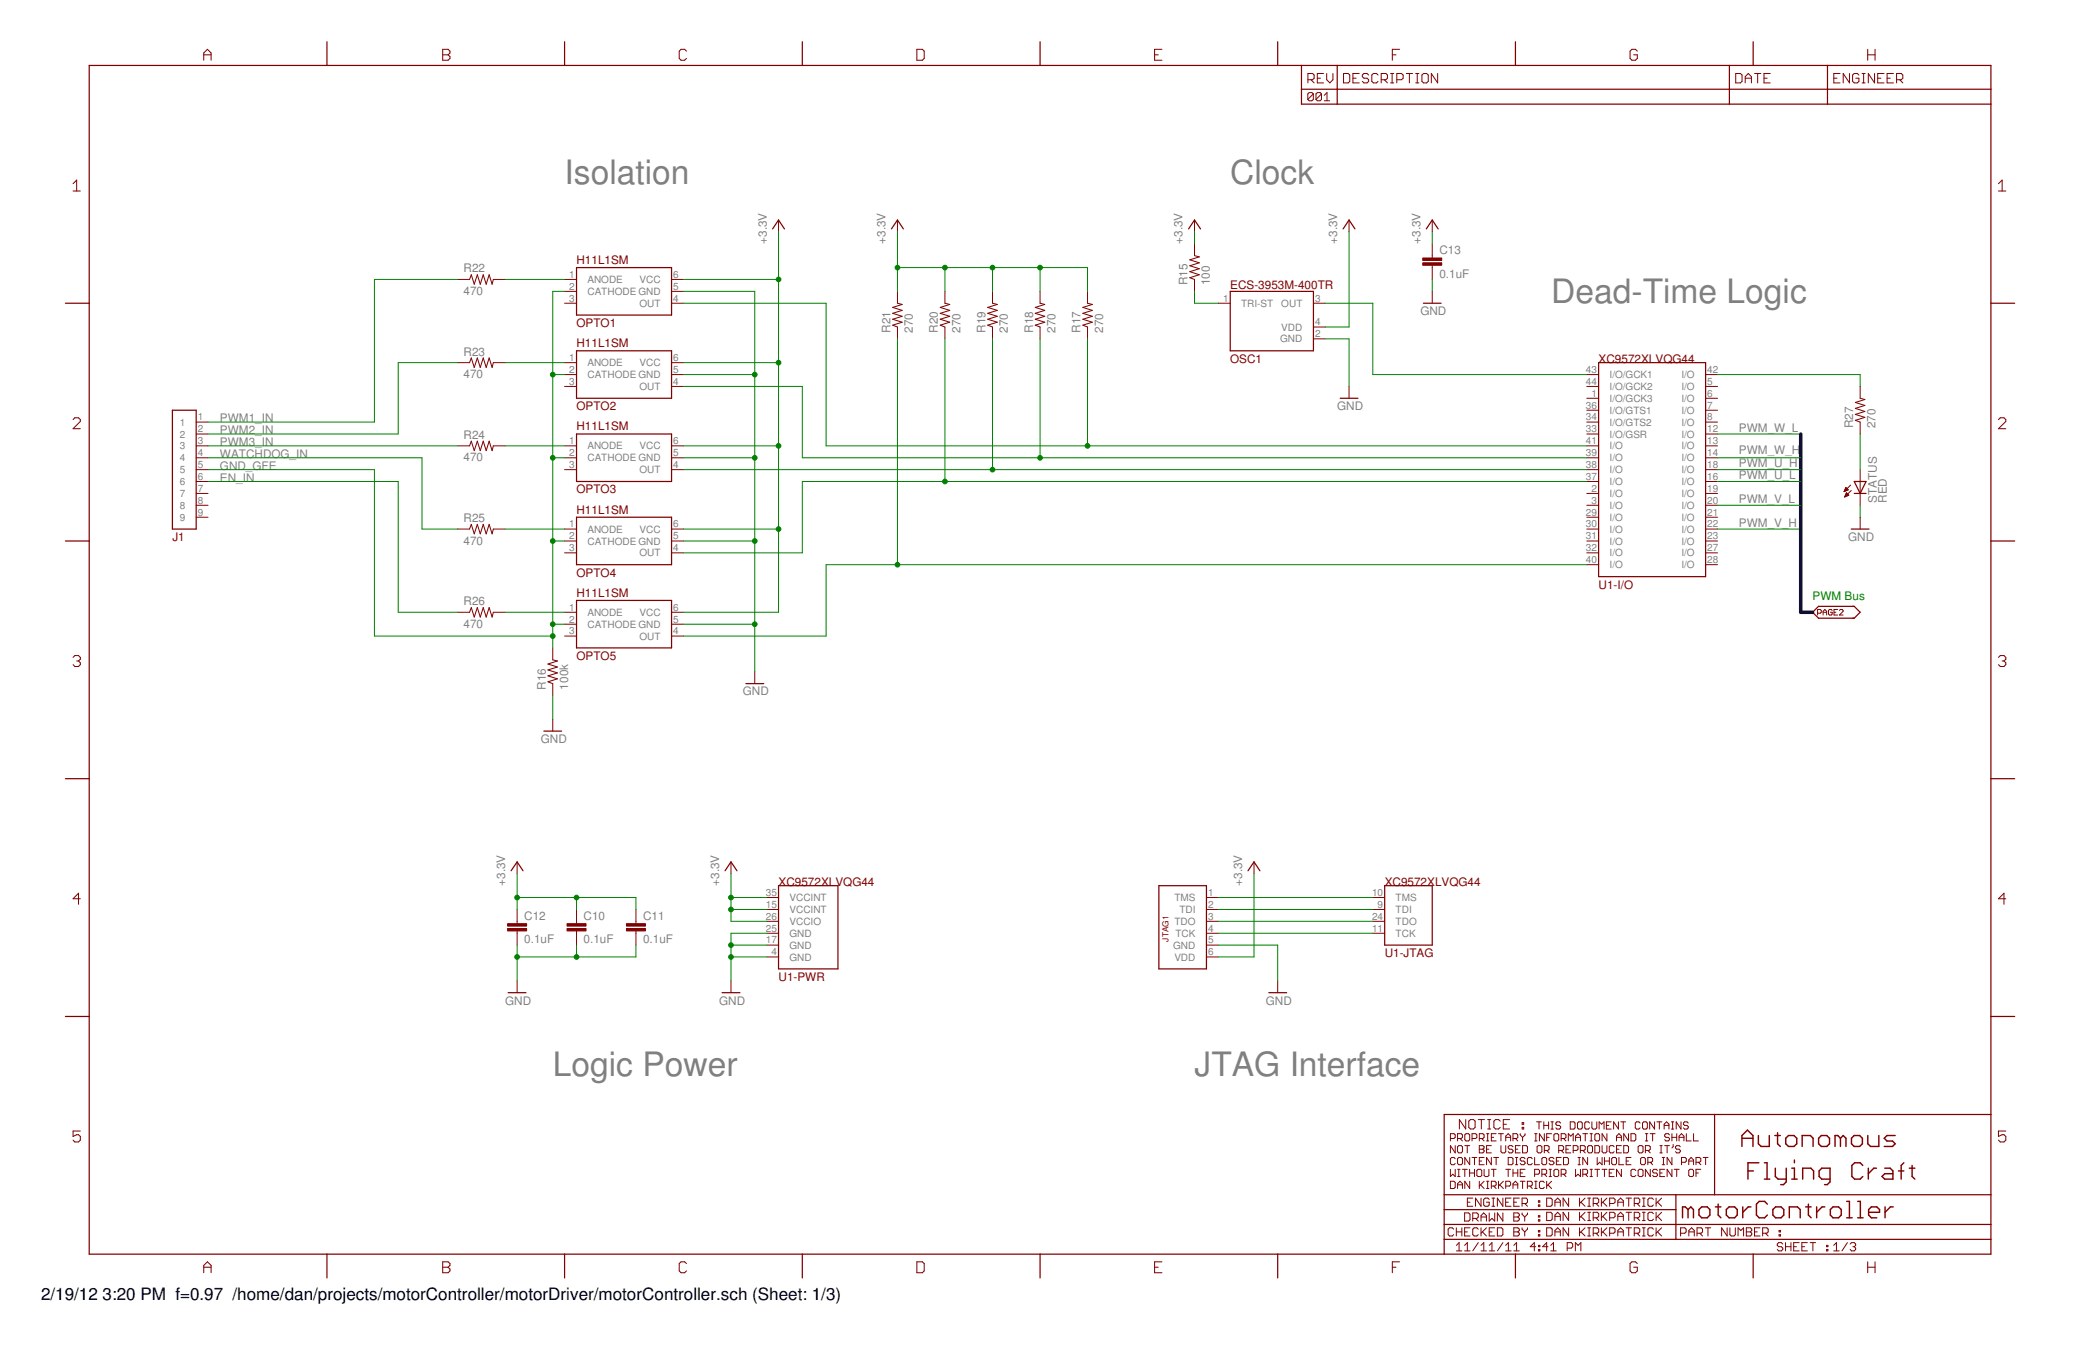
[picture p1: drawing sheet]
<svg xmlns="http://www.w3.org/2000/svg" width="431mm" height="279mm" viewBox="0 0 431 279" stroke-linecap="round" stroke-linejoin="round" font-family="sans-serif">
<defs><g id="words">
<g font-size="7" fill="#808080">
<text x="117.1" y="38.2">Isolation</text>
<text x="255.1" y="38.2">Clock</text>
<text x="321.6" y="62.9">Dead-Time Logic</text>
<text x="114.6" y="223">Logic Power</text>
<text x="247.7" y="223">JTAG Interface</text>
</g>
<g font-size="3.5">
<text x="8.5" y="269.5">2/19/12</text>
<text x="21.3" y="269.5">3:20 PM f=0.97 /home/dan/projects/motorController/motorDriver/motorController.sch (Sheet: 1/3)</text>
</g>
<g font-size="2.4" fill="#808080">
<text x="159" y="50.5" transform="rotate(-90 159 50.5)">+3.3V</text>
<text x="183.6" y="50.5" transform="rotate(-90 183.6 50.5)">+3.3V</text>
<text x="245.2" y="50.5" transform="rotate(-90 245.2 50.5)">+3.3V</text>
<text x="277.3" y="50.5" transform="rotate(-90 277.3 50.5)">+3.3V</text>
<text x="294.5" y="50.5" transform="rotate(-90 294.5 50.5)">+3.3V</text>
<text x="298.5" y="52.6">C13</text>
<text x="96.1" y="56.5">R22</text>
<text x="246.2" y="59.2" transform="rotate(-90 246.2 59.2)">R15</text>
<text x="250.9" y="59.2" transform="rotate(-90 250.9 59.2)">100</text>
<text x="298.5" y="57.6">0.1uF</text>
<text x="96.1" y="61.1">470</text>
<text x="294.5" y="65.3">GND</text>
<text x="184.6" y="69" transform="rotate(-90 184.6 69)">R21</text>
<text x="189.3" y="69" transform="rotate(-90 189.3 69)">270</text>
<text x="194.5" y="69" transform="rotate(-90 194.5 69)">R20</text>
<text x="199.1" y="69" transform="rotate(-90 199.1 69)">270</text>
<text x="204.3" y="69" transform="rotate(-90 204.3 69)">R19</text>
<text x="209" y="69" transform="rotate(-90 209 69)">270</text>
<text x="214.2" y="69" transform="rotate(-90 214.2 69)">R18</text>
<text x="218.9" y="69" transform="rotate(-90 218.9 69)">270</text>
<text x="224.1" y="69" transform="rotate(-90 224.1 69)">R17</text>
<text x="228.7" y="69" transform="rotate(-90 228.7 69)">270</text>
<text x="96.1" y="73.7">R23</text>
<text x="96.1" y="78.4">470</text>
<text x="45.6" y="87.5">PWM1_IN</text>
<text x="45.6" y="90">PWM2_IN</text>
<text x="277.3" y="85">GND</text>
<text x="360.6" y="89.5">PWM_W_L</text>
<text x="384.3" y="88.7" transform="rotate(-90 384.3 88.7)">R27</text>
<text x="388.9" y="88.7" transform="rotate(-90 388.9 88.7)">270</text>
<text x="45.6" y="94.9">WATCHDOG_IN</text>
<text x="45.6" y="92.4">PWM3_IN</text>
<text x="96.1" y="95.6">470</text>
<text x="96.1" y="91">R24</text>
<text x="360.6" y="94.2">PWM_W_H</text>
<text x="45.6" y="97.4">GND_GFE</text>
<text x="45.6" y="99.8">EN_IN</text>
<text x="360.6" y="96.9">PWM_U_H</text>
<text x="360.6" y="99.3">PWM_U_L</text>
<text x="360.6" y="104.3">PWM_V_L</text>
<text x="389.2" y="104.3" transform="rotate(-90 389.2 104.3)">STATUS</text>
<text x="391.3" y="104.3" transform="rotate(-90 391.3 104.3)">RED</text>
<text x="96.1" y="112.9">470</text>
<text x="96.1" y="108.2">R25</text>
<text x="360.6" y="109.2">PWM_V_H</text>
<text x="383.2" y="112.2">GND</text>
<text x="96.1" y="125.5">R26</text>
<text x="96.1" y="130.1">470</text>
<text x="113.2" y="143" transform="rotate(-90 113.2 143)">R16</text>
<text x="117.8" y="143" transform="rotate(-90 117.8 143)">100k</text>
<text x="154" y="144.2">GND</text>
<text x="112.1" y="154">GND</text>
<text x="104.8" y="183.6" transform="rotate(-90 104.8 183.6)">+3.3V</text>
<text x="149.1" y="183.6" transform="rotate(-90 149.1 183.6)">+3.3V</text>
<text x="257.6" y="183.6" transform="rotate(-90 257.6 183.6)">+3.3V</text>
<text x="108.7" y="190.6">C12</text>
<text x="121" y="190.6">C10</text>
<text x="133.3" y="190.6">C11</text>
<text x="108.7" y="195.6">0.1uF</text>
<text x="121" y="195.6">0.1uF</text>
<text x="133.3" y="195.6">0.1uF</text>
<text x="104.8" y="208.3">GND</text>
<text x="149.1" y="208.3">GND</text>
<text x="262.5" y="208.3">GND</text>
</g>
<g font-size="2.4" fill="#800000">
<text x="119.5" y="54.7">H11L1SM</text>
<text x="255.1" y="59.9">ECS-3953M-400TR</text>
<text x="119.5" y="67.8">OPTO1</text>
<text x="119.5" y="72">H11L1SM</text>
<text x="255.1" y="75.2">OSC1</text>
<text x="331.5" y="75.2">XC9572XLVQG44</text>
<text x="119.5" y="85">OPTO2</text>
<text x="119.5" y="89.2">H11L1SM</text>
<text x="119.5" y="102.3">OPTO3</text>
<text x="119.5" y="106.5">H11L1SM</text>
<text x="35.7" y="112.2">J1</text>
<text x="119.5" y="119.5">OPTO4</text>
<text x="119.5" y="123.7">H11L1SM</text>
<text x="331.5" y="122">U1-I/O</text>
<text x="119.5" y="136.8">OPTO5</text>
<text x="161.4" y="183.6">XC9572XLVQG44</text>
<text x="287.1" y="183.6">XC9572XLVQG44</text>
<text x="161.4" y="203.3">U1-PWR</text>
<text x="287.1" y="198.4">U1-JTAG</text>
</g>
<text font-size="2.4" fill="#008000" x="375.9" y="124.5">PWM Bus</text>
<g font-size="2.1" fill="#808080">
<text x="118.1" y="57.6">1</text>
<text x="121.8" y="58.7">ANODE</text>
<text x="132.6" y="58.7">VCC</text>
<text x="139.6" y="57.6">6</text>
<text x="118.1" y="60.1">2</text>
<text x="118.1" y="62.5">3</text>
<text x="121.8" y="61.1">CATHODE GND</text>
<text x="132.6" y="63.6">OUT</text>
<text x="139.6" y="60.1">5</text>
<text x="139.6" y="62.5">4</text>
<text x="253.6" y="62.5">1</text>
<text x="257.4" y="63.6">TRI-ST</text>
<text x="265.7" y="63.6">OUT</text>
<text x="272.7" y="62.5">3</text>
<text x="265.5" y="71">GND</text>
<text x="265.7" y="68.5">VDD</text>
<text x="272.7" y="69.9">2</text>
<text x="272.7" y="67.4">4</text>
<text x="118.1" y="74.8">1</text>
<text x="118.1" y="77.3">2</text>
<text x="121.8" y="75.9">ANODE</text>
<text x="132.6" y="75.9">VCC</text>
<text x="139.6" y="74.8">6</text>
<text x="139.6" y="77.3">5</text>
<text x="328.9" y="77.3">43</text>
<text x="354" y="77.3">42</text>
<text x="118.1" y="79.8">3</text>
<text x="121.8" y="78.4">CATHODE GND</text>
<text x="132.6" y="80.9">OUT</text>
<text x="139.6" y="79.8">4</text>
<text x="328.9" y="79.8">44</text>
<text x="330" y="82.2">1</text>
<text x="333.8" y="78.4">I/O/GCK1</text>
<text x="333.8" y="80.9">I/O/GCK2</text>
<text x="333.8" y="83.3">I/O/GCK3</text>
<text x="348.7" y="78.4">I/O</text>
<text x="348.7" y="83.3">I/O</text>
<text x="348.7" y="80.9">I/O</text>
<text x="354" y="82.2">6</text>
<text x="354" y="79.8">5</text>
<text x="37.3" y="88.2">1</text>
<text x="41" y="87.2">1</text>
<text x="41" y="89.6">2</text>
<text x="328.9" y="84.7">36</text>
<text x="328.9" y="87.2">34</text>
<text x="328.9" y="89.6">33</text>
<text x="333.8" y="85.8">I/O/GTS1</text>
<text x="333.8" y="88.2">I/O/GTS2</text>
<text x="348.7" y="88.2">I/O</text>
<text x="348.7" y="85.8">I/O</text>
<text x="354" y="89.6">12</text>
<text x="354" y="87.2">8</text>
<text x="354" y="84.7">7</text>
<text x="37.3" y="90.7">2</text>
<text x="37.3" y="93.2">3</text>
<text x="37.3" y="95.6">4</text>
<text x="41" y="92.1">3</text>
<text x="41" y="94.6">4</text>
<text x="118.1" y="92.1">1</text>
<text x="118.1" y="94.6">2</text>
<text x="121.8" y="93.2">ANODE</text>
<text x="121.8" y="95.6">CATHODE GND</text>
<text x="132.6" y="93.2">VCC</text>
<text x="139.6" y="92.1">6</text>
<text x="139.6" y="94.6">5</text>
<text x="328.9" y="94.6">39</text>
<text x="328.9" y="92.1">41</text>
<text x="333.8" y="90.7">I/O/GSR</text>
<text x="333.8" y="95.6">I/O</text>
<text x="333.8" y="93.2">I/O</text>
<text x="348.7" y="95.6">I/O</text>
<text x="348.7" y="93.2">I/O</text>
<text x="348.7" y="90.7">I/O</text>
<text x="354" y="94.6">14</text>
<text x="354" y="92.1">13</text>
<text x="37.3" y="98.1">5</text>
<text x="37.3" y="100.6">6</text>
<text x="41" y="97">5</text>
<text x="41" y="99.5">6</text>
<text x="41" y="101.9">7</text>
<text x="118.1" y="97">3</text>
<text x="132.6" y="98.1">OUT</text>
<text x="139.6" y="97">4</text>
<text x="328.9" y="99.5">37</text>
<text x="328.9" y="97">38</text>
<text x="330" y="101.9">2</text>
<text x="333.8" y="100.6">I/O</text>
<text x="333.8" y="98.1">I/O</text>
<text x="348.7" y="100.6">I/O</text>
<text x="348.7" y="98.1">I/O</text>
<text x="354" y="101.9">19</text>
<text x="354" y="99.5">16</text>
<text x="354" y="97">18</text>
<text x="37.3" y="103">7</text>
<text x="37.3" y="105.5">8</text>
<text x="37.3" y="108">9</text>
<text x="41" y="104.4">8</text>
<text x="41" y="106.9">9</text>
<text x="328.9" y="106.9">29</text>
<text x="330" y="104.4">3</text>
<text x="333.8" y="103">I/O</text>
<text x="333.8" y="105.5">I/O</text>
<text x="333.8" y="108">I/O</text>
<text x="348.7" y="108">I/O</text>
<text x="348.7" y="105.5">I/O</text>
<text x="348.7" y="103">I/O</text>
<text x="354" y="106.9">21</text>
<text x="354" y="104.4">20</text>
<text x="118.1" y="109.3">1</text>
<text x="118.1" y="111.8">2</text>
<text x="121.8" y="110.4">ANODE</text>
<text x="121.8" y="112.9">CATHODE GND</text>
<text x="132.6" y="110.4">VCC</text>
<text x="139.6" y="109.3">6</text>
<text x="139.6" y="111.8">5</text>
<text x="328.9" y="109.3">30</text>
<text x="328.9" y="111.8">31</text>
<text x="333.8" y="110.4">I/O</text>
<text x="333.8" y="112.9">I/O</text>
<text x="348.7" y="112.9">I/O</text>
<text x="348.7" y="110.4">I/O</text>
<text x="354" y="111.8">23</text>
<text x="354" y="109.3">22</text>
<text x="118.1" y="114.3">3</text>
<text x="132.6" y="115.4">OUT</text>
<text x="139.6" y="114.3">4</text>
<text x="328.9" y="116.7">40</text>
<text x="328.9" y="114.3">32</text>
<text x="333.8" y="117.8">I/O</text>
<text x="333.8" y="115.4">I/O</text>
<text x="348.7" y="117.8">I/O</text>
<text x="348.7" y="115.4">I/O</text>
<text x="354" y="116.7">28</text>
<text x="354" y="114.3">27</text>
<text x="118.1" y="126.6">1</text>
<text x="118.1" y="129.1">2</text>
<text x="118.1" y="131.5">3</text>
<text x="121.8" y="127.7">ANODE</text>
<text x="121.8" y="130.1">CATHODE GND</text>
<text x="132.6" y="127.7">VCC</text>
<text x="139.6" y="126.6">6</text>
<text x="139.6" y="129.1">5</text>
<text x="139.6" y="131.5">4</text>
<text x="132.6" y="132.6">OUT</text>
<text x="158.8" y="185.7">35</text>
<text x="250.5" y="185.7">1</text>
<text x="284.5" y="185.7">10</text>
<text x="158.8" y="190.7">26</text>
<text x="158.8" y="188.2">15</text>
<text x="163.7" y="191.7">VCCIO</text>
<text x="163.7" y="189.3">VCCINT</text>
<text x="163.7" y="186.8">VCCINT</text>
<text x="243.5" y="191.8">TDO</text>
<text x="243.5" y="186.8">TMS</text>
<text x="244.5" y="189.3">TDI</text>
<text x="250.5" y="188.2">2</text>
<text x="250.5" y="190.7">3</text>
<text x="284.5" y="190.7">24</text>
<text x="285.6" y="188.2">9</text>
<text x="289.4" y="189.3">TDI</text>
<text x="289.4" y="191.7">TDO</text>
<text x="289.4" y="186.8">TMS</text>
<text x="158.8" y="195.6">17</text>
<text x="158.8" y="193.1">25</text>
<text x="163.7" y="196.7">GND</text>
<text x="163.7" y="194.2">GND</text>
<text x="243.3" y="196.7">GND</text>
<text x="243.7" y="194.2">TCK</text>
<text x="250.5" y="193.1">4</text>
<text x="250.5" y="195.6">5</text>
<text x="284.5" y="193.1">11</text>
<text x="289.4" y="194.2">TCK</text>
<text x="160" y="198.1">4</text>
<text x="163.7" y="199.1">GND</text>
<text x="243.5" y="199.1">VDD</text>
<text x="250.5" y="198.1">6</text>
</g>
<text font-size="1.7" fill="#800000" x="242.3" y="195.2" transform="rotate(-90 242.3 195.2)">JTAG1</text>
</g></defs>
<g fill="#800000" stroke="#800000" stroke-width=".21">
<path d="M142 261.6l.3 .4z"/>
<path d="M141.2 261.6h.8z"/>
<path d="M140.8 262l.4-.4z"/>
<path d="M140.8 262v1.5z"/>
<path d="M140.8 263.5l.4 .4z"/>
<path d="M141.2 263.9h.8z"/>
<path d="M142 263.9l.3-.4z"/>
<path d="M91.8 261.6v2.3z"/>
<path d="M91.8 261.6h1.1z"/>
<path d="M92.9 261.6l.4 .4z"/>
<path d="M93.3 262v.3z"/>
<path d="M93.3 262.3l-.4 .4z"/>
<path d="M92.9 262.7l.4 .4z"/>
<path d="M93.3 263.1v.4z"/>
<path d="M93.3 263.5l-.4 .4z"/>
<path d="M91.8 263.9h1.1z"/>
<path d="M91.8 262.7h1.1z"/>
<path d="M42.2 262.3v1.6z"/>
<path d="M42.2 262.3l.8-.7z"/>
<path d="M43 261.6l.8 .7z"/>
<path d="M43.8 262.3v1.6z"/>
<path d="M42.2 262.7h1.6z"/>
<path d="M190.1 261.6v2.3z"/>
<path d="M190.1 263.9h1.2z"/>
<path d="M191.3 263.9l.3-.4z"/>
<path d="M191.6 262v1.5z"/>
<path d="M191.3 261.6l.3 .4z"/>
<path d="M190.1 261.6h1.2z"/>
<path d="M239.4 261.6h1.5z"/>
<path d="M239.4 261.6v2.3z"/>
<path d="M239.4 263.9h1.5z"/>
<path d="M239.4 262.7h.8z"/>
<path d="M288.7 261.6v2.3z"/>
<path d="M288.7 261.6h1.5z"/>
<path d="M288.7 262.7h.8z"/>
<path d="M339.1 261.6l.4 .4z"/>
<path d="M338.4 261.6h.7z"/>
<path d="M338 262l.4-.4z"/>
<path d="M338 262v1.5z"/>
<path d="M338 263.5l.4 .4z"/>
<path d="M338.4 263.9h.7z"/>
<path d="M339.1 263.9l.4-.4z"/>
<path d="M339.5 262.7v.8z"/>
<path d="M338.7 262.7h.8z"/>
<path d="M387.3 261.6v2.3z"/>
<path d="M387.3 262.7h1.5z"/>
<path d="M388.8 261.6v2.3z"/>
<path d="M414.4 38.1l.8-.8z"/>
<path d="M415.2 37.3v2.3z"/>
<path d="M414.4 39.6h1.5z"/>
<path d="M414.4 88.9h1.5z"/>
<path d="M414.4 88.9l1.5-1.5z"/>
<path d="M415.9 87v.4z"/>
<path d="M415.5 86.6l.4 .4z"/>
<path d="M414.8 86.6h.7z"/>
<path d="M414.8 86.6l-.4 .4z"/>
<path d="M414.4 136.3l.4-.4z"/>
<path d="M414.8 135.9h.7z"/>
<path d="M415.5 135.9l.4 .4z"/>
<path d="M415.9 136.3v.4z"/>
<path d="M415.5 137l.4-.3z"/>
<path d="M415.2 137h.3z"/>
<path d="M415.5 137l.4 .4z"/>
<path d="M415.9 137.4v.4z"/>
<path d="M415.9 137.8l-.4 .4z"/>
<path d="M414.8 138.2h.7z"/>
<path d="M414.4 137.8l.4 .4z"/>
<path d="M415.5 185.2v2.3z"/>
<path d="M415.5 185.2l-1.1 1.1z"/>
<path d="M414.4 186.3h1.5z"/>
<path d="M414.4 234.5h1.5z"/>
<path d="M414.4 234.5v1.1z"/>
<path d="M414.4 235.6l.8-.4z"/>
<path d="M415.2 235.2h.3z"/>
<path d="M415.5 235.2l.4 .4z"/>
<path d="M415.9 235.6v.8z"/>
<path d="M415.9 236.4l-.4 .3z"/>
<path d="M414.8 236.7h.7z"/>
<path d="M414.4 236.4l.4 .3z"/>
<path d="M15.9 37.3l-.7 .8z"/>
<path d="M15.9 37.3v2.3z"/>
<path d="M15.2 39.6h1.5z"/>
<path d="M15.2 88.9h1.5z"/>
<path d="M15.2 88.9l1.5-1.5z"/>
<path d="M16.7 87v.4z"/>
<path d="M16.3 86.6l.4 .4z"/>
<path d="M15.5 86.6h.8z"/>
<path d="M15.5 86.6l-.3 .4z"/>
<path d="M15.5 135.9l-.3 .4z"/>
<path d="M15.5 135.9h.8z"/>
<path d="M16.3 135.9l.4 .4z"/>
<path d="M16.7 136.3v.4z"/>
<path d="M16.3 137l.4-.3z"/>
<path d="M15.9 137h.4z"/>
<path d="M16.3 137l.4 .4z"/>
<path d="M16.7 137.4v.4z"/>
<path d="M16.7 137.8l-.4 .4z"/>
<path d="M15.5 138.2h.8z"/>
<path d="M15.2 137.8l.3 .4z"/>
<path d="M16.3 185.2v2.3z"/>
<path d="M16.3 185.2l-1.1 1.1z"/>
<path d="M15.2 186.3h1.5z"/>
<path d="M15.2 234.5h1.5z"/>
<path d="M15.2 234.5v1.1z"/>
<path d="M15.2 235.6l.7-.4z"/>
<path d="M15.9 235.2h.4z"/>
<path d="M16.3 235.2l.4 .4z"/>
<path d="M16.7 235.6v.8z"/>
<path d="M16.7 236.4l-.4 .3z"/>
<path d="M15.5 236.7h.8z"/>
<path d="M15.2 236.4l.3 .3z"/>
<path d="M142 10.2l.3 .4z"/>
<path d="M141.2 10.2h.8z"/>
<path d="M141.2 10.2l-.4 .4z"/>
<path d="M140.8 10.6v1.5z"/>
<path d="M140.8 12.1l.4 .4z"/>
<path d="M141.2 12.5h.8z"/>
<path d="M142 12.5l.3-.4z"/>
<path d="M91.8 10.2v2.3z"/>
<path d="M91.8 10.2h1.1z"/>
<path d="M92.9 10.2l.4 .4z"/>
<path d="M93.3 10.6v.4z"/>
<path d="M93.3 11l-.4 .4z"/>
<path d="M92.9 11.4l.4 .3z"/>
<path d="M93.3 11.7v.4z"/>
<path d="M93.3 12.1l-.4 .4z"/>
<path d="M91.8 12.5h1.1z"/>
<path d="M91.8 11.4h1.1z"/>
<path d="M42.2 11v1.5z"/>
<path d="M42.2 11l.8-.8z"/>
<path d="M43 10.2l.8 .8z"/>
<path d="M43.8 11v1.5z"/>
<path d="M42.2 11.4h1.6z"/>
<path d="M190.1 10.2v2.3z"/>
<path d="M190.1 12.5h1.2z"/>
<path d="M191.3 12.5l.3-.4z"/>
<path d="M191.6 10.6v1.5z"/>
<path d="M191.3 10.2l.3 .4z"/>
<path d="M190.1 10.2h1.2z"/>
<path d="M239.4 10.2h1.5z"/>
<path d="M239.4 10.2v2.3z"/>
<path d="M239.4 12.5h1.5z"/>
<path d="M239.4 11.4h.8z"/>
<path d="M288.7 10.2v2.3z"/>
<path d="M288.7 10.2h1.5z"/>
<path d="M288.7 11.4h.8z"/>
<path d="M339.1 10.2l.4 .4z"/>
<path d="M338.4 10.2h.7z"/>
<path d="M338 10.6l.4-.4z"/>
<path d="M338 10.6v1.5z"/>
<path d="M338 12.1l.4 .4z"/>
<path d="M338.4 12.5h.7z"/>
<path d="M339.1 12.5l.4-.4z"/>
<path d="M339.5 11.4v.7z"/>
<path d="M338.7 11.4h.8z"/>
<path d="M387.3 10.2v2.3z"/>
<path d="M387.3 11.4h1.5z"/>
<path d="M388.8 10.2v2.3z"/>
<path d="M271.2 15.2v2z"/>
<path d="M271.2 15.2h1z"/>
<path d="M272.2 15.2l.3 .4z"/>
<path d="M272.5 15.6v.6z"/>
<path d="M272.5 16.2l-.3 .3z"/>
<path d="M271.2 16.5h1z"/>
<path d="M271.8 16.5l.7 .7z"/>
<path d="M273.2 15.2h1.2z"/>
<path d="M273.2 15.2v2z"/>
<path d="M273.2 17.2h1.2z"/>
<path d="M273.2 16.2h.6z"/>
<path d="M275.1 15.2v1.3z"/>
<path d="M275.1 16.5l.7 .7z"/>
<path d="M276.4 16.5l-.6 .7z"/>
<path d="M276.4 15.2v1.3z"/>
<path d="M278.6 15.2v2z"/>
<path d="M278.6 17.2h1z"/>
<path d="M279.9 16.9l-.3 .3z"/>
<path d="M279.9 15.6v1.3z"/>
<path d="M279.6 15.2l.3 .4z"/>
<path d="M278.6 15.2h1z"/>
<path d="M280.5 15.2h1.4z"/>
<path d="M280.5 15.2v2z"/>
<path d="M280.5 17.2h1.4z"/>
<path d="M280.5 16.2h.7z"/>
<path d="M283.5 15.2l.3 .4z"/>
<path d="M282.8 15.2h.7z"/>
<path d="M282.5 15.6l.3-.4z"/>
<path d="M282.5 15.6v.3z"/>
<path d="M282.5 15.9l.3 .3z"/>
<path d="M282.8 16.2h.7z"/>
<path d="M283.5 16.2l.3 .3z"/>
<path d="M283.8 16.5v.4z"/>
<path d="M283.5 17.2l.3-.3z"/>
<path d="M282.8 17.2h.7z"/>
<path d="M282.5 16.9l.3 .3z"/>
<path d="M285.4 15.2l.3 .4z"/>
<path d="M284.8 15.2h.6z"/>
<path d="M284.8 15.2l-.3 .4z"/>
<path d="M284.5 15.6v1.3z"/>
<path d="M284.5 16.9l.3 .3z"/>
<path d="M284.8 17.2h.6z"/>
<path d="M285.4 17.2l.3-.3z"/>
<path d="M286.4 15.2v2z"/>
<path d="M286.4 15.2h1z"/>
<path d="M287.4 15.2l.3 .4z"/>
<path d="M287.7 15.6v.6z"/>
<path d="M287.7 16.2l-.3 .3z"/>
<path d="M286.4 16.5h1z"/>
<path d="M287 16.5l.7 .7z"/>
<path d="M288.3 17.2h.7z"/>
<path d="M288.7 15.2v2z"/>
<path d="M288.3 15.2h.7z"/>
<path d="M289.6 15.2v2z"/>
<path d="M289.6 15.2h1z"/>
<path d="M290.6 15.2l.4 .4z"/>
<path d="M291 15.6v.6z"/>
<path d="M290.6 16.5l.4-.3z"/>
<path d="M289.6 16.5h1z"/>
<path d="M292.2 15.2v2z"/>
<path d="M291.6 15.2h1.3z"/>
<path d="M293.6 17.2h.6z"/>
<path d="M293.9 15.2v2z"/>
<path d="M293.6 15.2h.6z"/>
<path d="M295.2 15.2h.6z"/>
<path d="M294.8 15.6l.4-.4z"/>
<path d="M294.8 15.6v1.3z"/>
<path d="M294.8 16.9l.4 .3z"/>
<path d="M295.2 17.2h.6z"/>
<path d="M295.8 17.2l.4-.3z"/>
<path d="M296.2 15.6v1.3z"/>
<path d="M295.8 15.2l.4 .4z"/>
<path d="M296.8 15.2v2z"/>
<path d="M296.8 15.2l1.3 2z"/>
<path d="M298.1 15.2v2z"/>
<path d="M359.9 15.2v2z"/>
<path d="M359.9 17.2h1z"/>
<path d="M360.9 17.2l.3-.3z"/>
<path d="M361.2 15.6v1.3z"/>
<path d="M360.9 15.2l.3 .4z"/>
<path d="M359.9 15.2h1z"/>
<path d="M361.9 15.9v1.3z"/>
<path d="M362.5 15.2l-.6 .7z"/>
<path d="M362.5 15.2l.7 .7z"/>
<path d="M363.2 15.9v1.3z"/>
<path d="M361.9 16.2h1.3z"/>
<path d="M364.5 15.2v2z"/>
<path d="M363.8 15.2h1.3z"/>
<path d="M365.8 15.2h1.3z"/>
<path d="M365.8 15.2v2z"/>
<path d="M365.8 17.2h1.3z"/>
<path d="M365.8 16.2h.6z"/>
<path d="M380.3 15.2h1.2z"/>
<path d="M380.3 15.2v2z"/>
<path d="M380.3 17.2h1.2z"/>
<path d="M380.3 16.2h.6z"/>
<path d="M382.2 15.2v2z"/>
<path d="M382.2 15.2l1.3 2z"/>
<path d="M383.5 15.2v2z"/>
<path d="M385.1 15.2l.4 .4z"/>
<path d="M384.5 15.2h.6z"/>
<path d="M384.1 15.6l.4-.4z"/>
<path d="M384.1 15.6v1.3z"/>
<path d="M384.1 16.9l.4 .3z"/>
<path d="M384.5 17.2h.6z"/>
<path d="M385.1 17.2l.4-.3z"/>
<path d="M385.5 16.2v.7z"/>
<path d="M384.8 16.2h.7z"/>
<path d="M386.1 17.2h.7z"/>
<path d="M386.4 15.2v2z"/>
<path d="M386.1 15.2h.7z"/>
<path d="M387.4 15.2v2z"/>
<path d="M387.4 15.2l1.3 2z"/>
<path d="M388.7 15.2v2z"/>
<path d="M389.4 15.2h1.3z"/>
<path d="M389.4 15.2v2z"/>
<path d="M389.4 17.2h1.3z"/>
<path d="M389.4 16.2h.6z"/>
<path d="M391.3 15.2h1.3z"/>
<path d="M391.3 15.2v2z"/>
<path d="M391.3 17.2h1.3z"/>
<path d="M391.3 16.2h.7z"/>
<path d="M393.3 15.2v2z"/>
<path d="M393.3 15.2h.9z"/>
<path d="M394.2 15.2l.4 .4z"/>
<path d="M394.6 15.6v.6z"/>
<path d="M394.6 16.2l-.4 .3z"/>
<path d="M393.3 16.5h.9z"/>
<path d="M393.9 16.5l.7 .7z"/>
<path d="M303.7 251.5v1.6z"/>
<path d="M303.7 253.1h.8z"/>
<path d="M304.5 253.1l.3-.2z"/>
<path d="M304.8 251.7v1.2z"/>
<path d="M304.5 251.5l.3 .2z"/>
<path d="M303.7 251.5h.8z"/>
<path d="M305.4 251.5v1.6z"/>
<path d="M305.4 251.5h.8z"/>
<path d="M306.2 251.5l.3 .2z"/>
<path d="M306.5 251.7v.6z"/>
<path d="M306.5 252.3l-.3 .3z"/>
<path d="M305.4 252.6h.8z"/>
<path d="M306 252.6l.5 .5z"/>
<path d="M307.1 252v1.1z"/>
<path d="M307.7 251.5l-.6 .5z"/>
<path d="M307.7 251.5l.5 .5z"/>
<path d="M308.2 252v1.1z"/>
<path d="M307.1 252.3h1.1z"/>
<path d="M308.8 251.5v1.6z"/>
<path d="M308.8 253.1l.6-.5z"/>
<path d="M309.4 252.6l.5 .5z"/>
<path d="M309.9 251.5v1.6z"/>
<path d="M310.5 251.5v1.6z"/>
<path d="M310.5 251.5l1.1 1.6z"/>
<path d="M311.6 251.5v1.6z"/>
<path d="M313.9 251.5v1.6z"/>
<path d="M313.9 251.5h.8z"/>
<path d="M314.7 251.5l.3 .2z"/>
<path d="M315 251.7v.3z"/>
<path d="M314.7 252.3l.3-.3z"/>
<path d="M314.7 252.3l.3 .3z"/>
<path d="M315 252.6v.3z"/>
<path d="M314.7 253.1l.3-.2z"/>
<path d="M313.9 253.1h.8z"/>
<path d="M313.9 252.3h.8z"/>
<path d="M315.6 251.5v.2z"/>
<path d="M315.6 251.7l.6 .6z"/>
<path d="M316.2 252.3l.5-.6z"/>
<path d="M316.7 251.5v.2z"/>
<path d="M316.2 252.3v.8z"/>
<path d="M319 252h.3z"/>
<path d="M319.3 252v.3z"/>
<path d="M319 252.3h.3z"/>
<path d="M319 252v.3z"/>
<path d="M319 252.9h.3z"/>
<path d="M319.3 252.9v.2z"/>
<path d="M319 253.1h.3z"/>
<path d="M319 252.9v.2z"/>
<path d="M301.1 254.5l.3 .3z"/>
<path d="M300.6 254.5h.5z"/>
<path d="M300.6 254.5l-.3 .3z"/>
<path d="M300.3 254.8v1.2z"/>
<path d="M300.3 256l.3 .2z"/>
<path d="M300.6 256.2h.5z"/>
<path d="M301.1 256.2l.3-.2z"/>
<path d="M302 254.5v1.7z"/>
<path d="M302 255.4h1.1z"/>
<path d="M303.1 254.5v1.7z"/>
<path d="M303.7 254.5h1.1z"/>
<path d="M303.7 254.5v1.7z"/>
<path d="M303.7 256.2h1.1z"/>
<path d="M303.7 255.4h.6z"/>
<path d="M306.2 254.5l.3 .3z"/>
<path d="M305.7 254.5h.5z"/>
<path d="M305.4 254.8l.3-.3z"/>
<path d="M305.4 254.8v1.2z"/>
<path d="M305.4 256l.3 .2z"/>
<path d="M305.7 256.2h.5z"/>
<path d="M306.2 256.2l.3-.2z"/>
<path d="M307.1 254.5v1.7z"/>
<path d="M307.1 255.7l1.1-1.2z"/>
<path d="M307.4 255.4l.8 .8z"/>
<path d="M308.8 254.5h1.1z"/>
<path d="M308.8 254.5v1.7z"/>
<path d="M308.8 256.2h1.1z"/>
<path d="M308.8 255.4h.6z"/>
<path d="M310.5 254.5v1.7z"/>
<path d="M310.5 256.2h.9z"/>
<path d="M311.4 256.2l.2-.2z"/>
<path d="M311.6 254.8v1.2z"/>
<path d="M311.4 254.5l.2 .3z"/>
<path d="M310.5 254.5h.9z"/>
<path d="M313.9 254.5v1.7z"/>
<path d="M313.9 254.5h.8z"/>
<path d="M314.7 254.5l.3 .3z"/>
<path d="M315 254.8v.3z"/>
<path d="M315 255.1l-.3 .3z"/>
<path d="M314.7 255.4l.3 .3z"/>
<path d="M315 255.7v.3z"/>
<path d="M314.7 256.2l.3-.2z"/>
<path d="M313.9 256.2h.8z"/>
<path d="M313.9 255.4h.8z"/>
<path d="M315.6 254.5v.3z"/>
<path d="M315.6 254.8l.6 .6z"/>
<path d="M316.2 255.4l.5-.6z"/>
<path d="M316.7 254.5v.3z"/>
<path d="M316.2 255.4v.8z"/>
<path d="M319 255.1h.3z"/>
<path d="M319.3 255.1v.3z"/>
<path d="M319 255.4h.3z"/>
<path d="M319 255.1v.3z"/>
<path d="M319 256h.3z"/>
<path d="M319.3 256v.2z"/>
<path d="M319 256.2h.3z"/>
<path d="M319 256v.2z"/>
<path d="M304.3 248.4h1.1z"/>
<path d="M304.3 248.4v1.7z"/>
<path d="M304.3 250.1h1.1z"/>
<path d="M304.3 249.2h.5z"/>
<path d="M306 248.4v1.7z"/>
<path d="M306 248.4l1.1 1.7z"/>
<path d="M307.1 248.4v1.7z"/>
<path d="M308.5 248.4l.3 .3z"/>
<path d="M307.9 248.4h.6z"/>
<path d="M307.7 248.7l.2-.3z"/>
<path d="M307.7 248.7v1.1z"/>
<path d="M307.7 249.8l.2 .3z"/>
<path d="M307.9 250.1h.6z"/>
<path d="M308.5 250.1l.3-.3z"/>
<path d="M308.8 249.2v.6z"/>
<path d="M308.2 249.2h.6z"/>
<path d="M309.4 250.1h.5z"/>
<path d="M309.6 248.4v1.7z"/>
<path d="M309.4 248.4h.5z"/>
<path d="M310.5 248.4v1.7z"/>
<path d="M310.5 248.4l1.1 1.7z"/>
<path d="M311.6 248.4v1.7z"/>
<path d="M312.2 248.4h1.1z"/>
<path d="M312.2 248.4v1.7z"/>
<path d="M312.2 250.1h1.1z"/>
<path d="M312.2 249.2h.6z"/>
<path d="M313.9 248.4h1.1z"/>
<path d="M313.9 248.4v1.7z"/>
<path d="M313.9 250.1h1.1z"/>
<path d="M313.9 249.2h.6z"/>
<path d="M315.6 248.4v1.7z"/>
<path d="M315.6 248.4h.9z"/>
<path d="M316.5 248.4l.2 .3z"/>
<path d="M316.7 248.7v.5z"/>
<path d="M316.7 249.2l-.2 .3z"/>
<path d="M315.6 249.5h.9z"/>
<path d="M316.2 249.5l.5 .6z"/>
<path d="M319 248.9h.3z"/>
<path d="M319.3 248.9v.3z"/>
<path d="M319 249.2h.3z"/>
<path d="M319 248.9v.3z"/>
<path d="M319 249.8h.3z"/>
<path d="M319.3 249.8v.3z"/>
<path d="M319 250.1h.3z"/>
<path d="M319 249.8v.3z"/>
<path d="M348.5 254.5v1.7z"/>
<path d="M348.5 254.5h.9z"/>
<path d="M349.4 254.5l.2 .3z"/>
<path d="M349.6 254.8v.6z"/>
<path d="M349.4 255.7l.2-.3z"/>
<path d="M348.5 255.7h.9z"/>
<path d="M350.2 255.1v1.1z"/>
<path d="M350.2 255.1l.6-.6z"/>
<path d="M350.8 254.5l.5 .6z"/>
<path d="M351.3 255.1v1.1z"/>
<path d="M350.2 255.4h1.1z"/>
<path d="M351.9 254.5v1.7z"/>
<path d="M351.9 254.5h.8z"/>
<path d="M352.7 254.5l.3 .3z"/>
<path d="M353 254.8v.6z"/>
<path d="M352.7 255.7l.3-.3z"/>
<path d="M351.9 255.7h.8z"/>
<path d="M352.5 255.7l.5 .5z"/>
<path d="M354.2 254.5v1.7z"/>
<path d="M353.6 254.5h1.1z"/>
<path d="M357 254.5v1.7z"/>
<path d="M357 254.5l1.1 1.7z"/>
<path d="M358.1 254.5v1.7z"/>
<path d="M358.7 254.5v1.5z"/>
<path d="M358.7 256l.3 .2z"/>
<path d="M359 256.2h.6z"/>
<path d="M359.6 256.2l.2-.2z"/>
<path d="M359.8 254.5v1.5z"/>
<path d="M360.4 254.5v1.7z"/>
<path d="M360.4 254.5l.6 .6z"/>
<path d="M361 255.1l.5-.6z"/>
<path d="M361.5 254.5v1.7z"/>
<path d="M362.1 254.5v1.7z"/>
<path d="M362.1 254.5h.9z"/>
<path d="M363 254.5l.2 .3z"/>
<path d="M363.2 254.8v.3z"/>
<path d="M363.2 255.1l-.2 .3z"/>
<path d="M363 255.4l.2 .3z"/>
<path d="M363.2 255.7v.3z"/>
<path d="M363.2 256l-.2 .2z"/>
<path d="M362.1 256.2h.9z"/>
<path d="M362.1 255.4h.9z"/>
<path d="M363.8 254.5h1.1z"/>
<path d="M363.8 254.5v1.7z"/>
<path d="M363.8 256.2h1.1z"/>
<path d="M363.8 255.4h.6z"/>
<path d="M365.5 254.5v1.7z"/>
<path d="M365.5 254.5h.9z"/>
<path d="M366.4 254.5l.2 .3z"/>
<path d="M366.6 254.8v.6z"/>
<path d="M366.6 255.4l-.2 .3z"/>
<path d="M365.5 255.7h.9z"/>
<path d="M366.1 255.7l.5 .5z"/>
<path d="M368.9 255.1h.3z"/>
<path d="M369.2 255.1v.3z"/>
<path d="M368.9 255.4h.3z"/>
<path d="M368.9 255.1v.3z"/>
<path d="M368.9 256h.3z"/>
<path d="M369.2 256v.2z"/>
<path d="M368.9 256.2h.3z"/>
<path d="M368.9 256v.2z"/>
<path d="M302.6 232.1v2z"/>
<path d="M302.6 232.1l1.3 2z"/>
<path d="M303.9 232.1v2z"/>
<path d="M304.9 232.1h.6z"/>
<path d="M304.6 232.4l.3-.3z"/>
<path d="M304.6 232.4v1.3z"/>
<path d="M304.6 233.7l.3 .4z"/>
<path d="M304.9 234.1h.6z"/>
<path d="M305.5 234.1l.4-.4z"/>
<path d="M305.9 232.4v1.3z"/>
<path d="M305.5 232.1l.4 .3z"/>
<path d="M307.2 232.1v2z"/>
<path d="M306.5 232.1h1.3z"/>
<path d="M308.5 234.1h.6z"/>
<path d="M308.8 232.1v2z"/>
<path d="M308.5 232.1h.6z"/>
<path d="M310.7 232.1l.4 .3z"/>
<path d="M310.1 232.1h.6z"/>
<path d="M309.8 232.4l.3-.3z"/>
<path d="M309.8 232.4v1.3z"/>
<path d="M309.8 233.7l.3 .4z"/>
<path d="M310.1 234.1h.6z"/>
<path d="M310.7 234.1l.4-.4z"/>
<path d="M311.7 232.1h1.3z"/>
<path d="M311.7 232.1v2z"/>
<path d="M311.7 234.1h1.3z"/>
<path d="M311.7 233.1h.7z"/>
<path d="M315.6 232.7h.3z"/>
<path d="M315.9 232.7v.4z"/>
<path d="M315.6 233.1h.3z"/>
<path d="M315.6 232.7v.4z"/>
<path d="M315.6 233.7h.3z"/>
<path d="M315.9 233.7v.4z"/>
<path d="M315.6 234.1h.3z"/>
<path d="M315.6 233.7v.4z"/>
<path d="M302.6 257.6l-.6 .6z"/>
<path d="M302.6 257.6v1.7z"/>
<path d="M302 259.3h1.1z"/>
<path d="M303.7 258.2l.6-.6z"/>
<path d="M304.3 257.6v1.7z"/>
<path d="M303.7 259.3h1.1z"/>
<path d="M306.5 257.6l-1.1 1.7z"/>
<path d="M307.1 258.2l.6-.6z"/>
<path d="M307.7 257.6v1.7z"/>
<path d="M307.1 259.3h1.1z"/>
<path d="M308.8 258.2l.6-.6z"/>
<path d="M309.4 257.6v1.7z"/>
<path d="M308.8 259.3h1.1z"/>
<path d="M311.6 257.6l-1.1 1.7z"/>
<path d="M312.2 258.2l.6-.6z"/>
<path d="M312.8 257.6v1.7z"/>
<path d="M312.2 259.3h1.1z"/>
<path d="M314.5 257.6l-.6 .6z"/>
<path d="M314.5 257.6v1.7z"/>
<path d="M313.9 259.3h1.1z"/>
<path d="M318.2 257.6v1.7z"/>
<path d="M318.2 257.6l-.9 .9z"/>
<path d="M317.3 258.5h1.1z"/>
<path d="M319 258.2h.3z"/>
<path d="M319.3 258.2v.3z"/>
<path d="M319 258.5h.3z"/>
<path d="M319 258.2v.3z"/>
<path d="M319 259h.3z"/>
<path d="M319.3 259v.3z"/>
<path d="M319 259.3h.3z"/>
<path d="M319 259v.3z"/>
<path d="M320.7 257.6v1.7z"/>
<path d="M320.7 257.6l-.8 .9z"/>
<path d="M319.9 258.5h1.1z"/>
<path d="M321.6 258.2l.5-.6z"/>
<path d="M322.1 257.6v1.7z"/>
<path d="M321.6 259.3h1.1z"/>
<path d="M325 257.6v1.7z"/>
<path d="M325 257.6h.8z"/>
<path d="M325.8 257.6l.3 .3z"/>
<path d="M326.1 257.9v.6z"/>
<path d="M326.1 258.5l-.3 .3z"/>
<path d="M325 258.8h.8z"/>
<path d="M326.7 257.6v1.7z"/>
<path d="M326.7 257.6l.5 .6z"/>
<path d="M327.2 258.2l.6-.6z"/>
<path d="M327.8 257.6v1.7z"/>
<path d="M369.4 257.6l.3 .3z"/>
<path d="M368.8 257.6h.6z"/>
<path d="M368.8 257.6l-.3 .3z"/>
<path d="M368.5 257.9v.3z"/>
<path d="M368.5 258.2l.3 .3z"/>
<path d="M368.8 258.5h.6z"/>
<path d="M369.4 258.5l.3 .3z"/>
<path d="M369.7 258.8v.2z"/>
<path d="M369.7 259l-.3 .3z"/>
<path d="M368.8 259.3h.6z"/>
<path d="M368.5 259l.3 .3z"/>
<path d="M370.2 257.6v1.7z"/>
<path d="M370.2 258.5h1.2z"/>
<path d="M371.4 257.6v1.7z"/>
<path d="M371.9 257.6h1.2z"/>
<path d="M371.9 257.6v1.7z"/>
<path d="M371.9 259.3h1.2z"/>
<path d="M371.9 258.5h.6z"/>
<path d="M373.6 257.6h1.2z"/>
<path d="M373.6 257.6v1.7z"/>
<path d="M373.6 259.3h1.2z"/>
<path d="M373.6 258.5h.6z"/>
<path d="M375.9 257.6v1.7z"/>
<path d="M375.3 257.6h1.2z"/>
<path d="M378.8 258.2h.2z"/>
<path d="M379 258.2v.3z"/>
<path d="M378.8 258.5h.2z"/>
<path d="M378.8 258.2v.3z"/>
<path d="M378.8 259h.2z"/>
<path d="M379 259v.3z"/>
<path d="M378.8 259.3h.2z"/>
<path d="M378.8 259v.3z"/>
<path d="M380.2 258.2l.6-.6z"/>
<path d="M380.8 257.6v1.7z"/>
<path d="M380.2 259.3h1.2z"/>
<path d="M383.1 257.6l-1.2 1.7z"/>
<path d="M383.6 257.9l.3-.3z"/>
<path d="M383.9 257.6h.6z"/>
<path d="M384.5 257.6l.3 .3z"/>
<path d="M384.8 257.9v.3z"/>
<path d="M384.5 258.5l.3-.3z"/>
<path d="M384.2 258.5h.3z"/>
<path d="M384.5 258.5l.3 .3z"/>
<path d="M384.8 258.8v.2z"/>
<path d="M384.8 259l-.3 .3z"/>
<path d="M383.9 259.3h.6z"/>
<path d="M383.6 259l.3 .3z"/>
<path d="M319.1 232.6v1.5z"/>
<path d="M318.6 232.6h1z"/>
<path d="M320.1 232.6v1.5z"/>
<path d="M320.1 233.3h1z"/>
<path d="M321.1 232.6v1.5z"/>
<path d="M321.6 234.1h.5z"/>
<path d="M321.9 232.6v1.5z"/>
<path d="M321.6 232.6h.5z"/>
<path d="M323.4 232.6l.2 .2z"/>
<path d="M322.8 232.6h.6z"/>
<path d="M322.8 232.6l-.2 .2z"/>
<path d="M322.6 232.8v.3z"/>
<path d="M322.6 233.1l.2 .2z"/>
<path d="M322.8 233.3h.6z"/>
<path d="M323.4 233.3l.2 .3z"/>
<path d="M323.6 233.6v.2z"/>
<path d="M323.6 233.8l-.2 .3z"/>
<path d="M322.8 234.1h.6z"/>
<path d="M322.6 233.8l.2 .3z"/>
<path d="M325.6 232.6v1.5z"/>
<path d="M325.6 234.1h.8z"/>
<path d="M326.6 233.8l-.2 .3z"/>
<path d="M326.6 232.8v1z"/>
<path d="M326.4 232.6l.2 .2z"/>
<path d="M325.6 232.6h.8z"/>
<path d="M327.4 232.6h.4z"/>
<path d="M327.1 232.8l.3-.2z"/>
<path d="M327.1 232.8v1z"/>
<path d="M327.1 233.8l.3 .3z"/>
<path d="M327.4 234.1h.4z"/>
<path d="M328.1 233.8l-.3 .3z"/>
<path d="M328.1 232.8v1z"/>
<path d="M327.8 232.6l.3 .2z"/>
<path d="M329.3 232.6l.3 .2z"/>
<path d="M328.8 232.6h.5z"/>
<path d="M328.8 232.6l-.2 .2z"/>
<path d="M328.6 232.8v1z"/>
<path d="M328.6 233.8l.2 .3z"/>
<path d="M328.8 234.1h.5z"/>
<path d="M329.3 234.1l.3-.3z"/>
<path d="M330.1 232.6v1.2z"/>
<path d="M330.1 233.8l.2 .3z"/>
<path d="M330.3 234.1h.6z"/>
<path d="M330.9 234.1l.2-.3z"/>
<path d="M331.1 232.6v1.2z"/>
<path d="M331.6 232.6v1.5z"/>
<path d="M331.6 232.6l.5 .5z"/>
<path d="M332.1 233.1l.5-.5z"/>
<path d="M332.6 232.6v1.5z"/>
<path d="M333.1 232.6h1z"/>
<path d="M333.1 232.6v1.5z"/>
<path d="M333.1 234.1h1z"/>
<path d="M333.1 233.3h.5z"/>
<path d="M334.6 232.6v1.5z"/>
<path d="M334.6 232.6l1 1.5z"/>
<path d="M335.6 232.6v1.5z"/>
<path d="M336.6 232.6v1.5z"/>
<path d="M336.1 232.6h1z"/>
<path d="M339.8 232.6l.3 .2z"/>
<path d="M339.3 232.6h.5z"/>
<path d="M339.3 232.6l-.2 .2z"/>
<path d="M339.1 232.8v1z"/>
<path d="M339.1 233.8l.2 .3z"/>
<path d="M339.3 234.1h.5z"/>
<path d="M339.8 234.1l.3-.3z"/>
<path d="M340.8 232.6h.5z"/>
<path d="M340.8 232.6l-.2 .2z"/>
<path d="M340.6 232.8v1z"/>
<path d="M340.6 233.8l.2 .3z"/>
<path d="M340.8 234.1h.5z"/>
<path d="M341.3 234.1l.3-.3z"/>
<path d="M341.6 232.8v1z"/>
<path d="M341.3 232.6l.3 .2z"/>
<path d="M342.1 232.6v1.5z"/>
<path d="M342.1 232.6l1 1.5z"/>
<path d="M343.1 232.6v1.5z"/>
<path d="M344.1 232.6v1.5z"/>
<path d="M343.6 232.6h1z"/>
<path d="M345.1 233.1v1z"/>
<path d="M345.1 233.1l.5-.5z"/>
<path d="M345.6 232.6l.5 .5z"/>
<path d="M346.1 233.1v1z"/>
<path d="M345.1 233.3h1z"/>
<path d="M346.6 234.1h.5z"/>
<path d="M346.8 232.6v1.5z"/>
<path d="M346.6 232.6h.5z"/>
<path d="M347.6 232.6v1.5z"/>
<path d="M347.6 232.6l1 1.5z"/>
<path d="M348.6 232.6v1.5z"/>
<path d="M349.8 232.6l.3 .2z"/>
<path d="M349.3 232.6h.5z"/>
<path d="M349.3 232.6l-.2 .2z"/>
<path d="M349.1 232.8v.3z"/>
<path d="M349.1 233.1l.2 .2z"/>
<path d="M349.3 233.3h.5z"/>
<path d="M349.8 233.3l.3 .3z"/>
<path d="M350.1 233.6v.2z"/>
<path d="M350.1 233.8l-.3 .3z"/>
<path d="M349.3 234.1h.5z"/>
<path d="M349.1 233.8l.2 .3z"/>
<path d="M300.8 235v1.5z"/>
<path d="M300.8 235h.7z"/>
<path d="M301.5 235l.2 .3z"/>
<path d="M301.7 235.3v.5z"/>
<path d="M301.5 236l.2-.2z"/>
<path d="M300.8 236h.7z"/>
<path d="M302.2 235v1.5z"/>
<path d="M302.2 235h.8z"/>
<path d="M303 235l.2 .3z"/>
<path d="M303.2 235.3v.5z"/>
<path d="M303 236l.2-.2z"/>
<path d="M302.2 236h.8z"/>
<path d="M302.7 236l.5 .5z"/>
<path d="M304 235h.5z"/>
<path d="M304 235l-.3 .3z"/>
<path d="M303.7 235.3v1z"/>
<path d="M303.7 236.3l.3 .2z"/>
<path d="M304 236.5h.5z"/>
<path d="M304.5 236.5l.3-.2z"/>
<path d="M304.8 235.3v1z"/>
<path d="M304.5 235l.3 .3z"/>
<path d="M305.2 235v1.5z"/>
<path d="M305.2 235h.8z"/>
<path d="M306 235l.2 .3z"/>
<path d="M306.2 235.3v.5z"/>
<path d="M306.2 235.8l-.2 .2z"/>
<path d="M305.2 236h.8z"/>
<path d="M306.7 235v1.5z"/>
<path d="M306.7 235h.8z"/>
<path d="M307.5 235l.2 .3z"/>
<path d="M307.7 235.3v.5z"/>
<path d="M307.5 236l.2-.2z"/>
<path d="M306.7 236h.8z"/>
<path d="M307.2 236l.5 .5z"/>
<path d="M308.2 236.5h.5z"/>
<path d="M308.5 235v1.5z"/>
<path d="M308.2 235h.5z"/>
<path d="M309.2 235h1z"/>
<path d="M309.2 235v1.5z"/>
<path d="M309.2 236.5h1z"/>
<path d="M309.2 235.8h.5z"/>
<path d="M311.2 235v1.5z"/>
<path d="M310.7 235h1z"/>
<path d="M312.2 235.5v1z"/>
<path d="M312.2 235.5l.5-.5z"/>
<path d="M312.7 235l.5 .5z"/>
<path d="M313.2 235.5v1z"/>
<path d="M312.2 235.8h1z"/>
<path d="M313.7 235v1.5z"/>
<path d="M313.7 235h.8z"/>
<path d="M314.5 235l.2 .3z"/>
<path d="M314.7 235.3v.5z"/>
<path d="M314.7 235.8l-.2 .2z"/>
<path d="M313.7 236h.8z"/>
<path d="M314.2 236l.5 .5z"/>
<path d="M315.2 235v.3z"/>
<path d="M315.2 235.3l.5 .5z"/>
<path d="M315.7 235.8l.5-.5z"/>
<path d="M316.2 235v.3z"/>
<path d="M315.7 235.8v.7z"/>
<path d="M318.2 236.5h.5z"/>
<path d="M318.5 235v1.5z"/>
<path d="M318.2 235h.5z"/>
<path d="M319.2 235v1.5z"/>
<path d="M319.2 235l1 1.5z"/>
<path d="M320.2 235v1.5z"/>
<path d="M320.7 235v1.5z"/>
<path d="M320.7 235h1z"/>
<path d="M320.7 235.8h.5z"/>
<path d="M322.5 235h.5z"/>
<path d="M322.5 235l-.3 .3z"/>
<path d="M322.2 235.3v1z"/>
<path d="M322.2 236.3l.3 .2z"/>
<path d="M322.5 236.5h.5z"/>
<path d="M323 236.5l.2-.2z"/>
<path d="M323.2 235.3v1z"/>
<path d="M323 235l.2 .3z"/>
<path d="M323.7 235v1.5z"/>
<path d="M323.7 235h.8z"/>
<path d="M324.5 235l.2 .3z"/>
<path d="M324.7 235.3v.5z"/>
<path d="M324.5 236l.2-.2z"/>
<path d="M323.7 236h.8z"/>
<path d="M324.2 236l.5 .5z"/>
<path d="M325.2 235v1.5z"/>
<path d="M325.2 235l.5 .5z"/>
<path d="M325.7 235.5l.5-.5z"/>
<path d="M326.2 235v1.5z"/>
<path d="M326.7 235.5v1z"/>
<path d="M326.7 235.5l.5-.5z"/>
<path d="M327.2 235l.5 .5z"/>
<path d="M327.7 235.5v1z"/>
<path d="M326.7 235.8h1z"/>
<path d="M328.7 235v1.5z"/>
<path d="M328.2 235h1z"/>
<path d="M329.7 236.5h.5z"/>
<path d="M330 235v1.5z"/>
<path d="M329.7 235h.5z"/>
<path d="M331 235h.4z"/>
<path d="M331 235l-.3 .3z"/>
<path d="M330.7 235.3v1z"/>
<path d="M330.7 236.3l.3 .2z"/>
<path d="M331 236.5h.4z"/>
<path d="M331.4 236.5l.3-.2z"/>
<path d="M331.7 235.3v1z"/>
<path d="M331.4 235l.3 .3z"/>
<path d="M332.2 235v1.5z"/>
<path d="M332.2 235l1 1.5z"/>
<path d="M333.2 235v1.5z"/>
<path d="M335.2 235.5v1z"/>
<path d="M335.2 235.5l.5-.5z"/>
<path d="M335.7 235l.5 .5z"/>
<path d="M336.2 235.5v1z"/>
<path d="M335.2 235.8h1z"/>
<path d="M336.7 235v1.5z"/>
<path d="M336.7 235l1 1.5z"/>
<path d="M337.7 235v1.5z"/>
<path d="M338.2 235v1.5z"/>
<path d="M338.2 236.5h.7z"/>
<path d="M338.9 236.5l.3-.2z"/>
<path d="M339.2 235.3v1z"/>
<path d="M338.9 235l.3 .3z"/>
<path d="M338.2 235h.7z"/>
<path d="M341.2 236.5h.5z"/>
<path d="M341.4 235v1.5z"/>
<path d="M341.2 235h.5z"/>
<path d="M342.7 235v1.5z"/>
<path d="M342.2 235h1z"/>
<path d="M345.9 235l.3 .3z"/>
<path d="M345.4 235h.5z"/>
<path d="M345.4 235l-.2 .3z"/>
<path d="M345.2 235.3v.2z"/>
<path d="M345.2 235.5l.2 .3z"/>
<path d="M345.4 235.8h.5z"/>
<path d="M345.9 235.8l.3 .2z"/>
<path d="M346.2 236v.3z"/>
<path d="M346.2 236.3l-.3 .2z"/>
<path d="M345.4 236.5h.5z"/>
<path d="M345.2 236.3l.2 .2z"/>
<path d="M346.7 235v1.5z"/>
<path d="M346.7 235.8h1z"/>
<path d="M347.7 235v1.5z"/>
<path d="M348.2 235.5v1z"/>
<path d="M348.2 235.5l.5-.5z"/>
<path d="M348.7 235l.5 .5z"/>
<path d="M349.2 235.5v1z"/>
<path d="M348.2 235.8h1z"/>
<path d="M349.7 235v1.5z"/>
<path d="M349.7 236.5h1z"/>
<path d="M351.2 235v1.5z"/>
<path d="M351.2 236.5h1z"/>
<path d="M300.8 237.5v1.5z"/>
<path d="M300.8 237.5l.9 1.5z"/>
<path d="M301.7 237.5v1.5z"/>
<path d="M302.5 237.5h.5z"/>
<path d="M302.2 237.7l.3-.2z"/>
<path d="M302.2 237.7v1.1z"/>
<path d="M302.2 238.8l.3 .2z"/>
<path d="M302.5 239h.5z"/>
<path d="M303 239l.2-.2z"/>
<path d="M303.2 237.7v1.1z"/>
<path d="M303 237.5l.2 .2z"/>
<path d="M304.2 237.5v1.5z"/>
<path d="M303.7 237.5h1.1z"/>
<path d="M306.7 237.5v1.5z"/>
<path d="M306.7 237.5h.8z"/>
<path d="M307.5 237.5l.2 .2z"/>
<path d="M307.7 237.7v.3z"/>
<path d="M307.7 238l-.2 .2z"/>
<path d="M307.5 238.2l.2 .3z"/>
<path d="M307.7 238.5v.3z"/>
<path d="M307.7 238.8l-.2 .2z"/>
<path d="M306.7 239h.8z"/>
<path d="M306.7 238.2h.8z"/>
<path d="M308.2 237.5h1z"/>
<path d="M308.2 237.5v1.5z"/>
<path d="M308.2 239h1z"/>
<path d="M308.2 238.2h.5z"/>
<path d="M311.2 237.5v1.3z"/>
<path d="M311.2 238.8l.3 .2z"/>
<path d="M311.5 239h.5z"/>
<path d="M312.2 238.8l-.2 .2z"/>
<path d="M312.2 237.5v1.3z"/>
<path d="M313.5 237.5l.2 .2z"/>
<path d="M313 237.5h.5z"/>
<path d="M312.7 237.7l.3-.2z"/>
<path d="M312.7 237.7v.3z"/>
<path d="M312.7 238l.3 .2z"/>
<path d="M313 238.2h.5z"/>
<path d="M313.5 238.2l.2 .3z"/>
<path d="M313.7 238.5v.3z"/>
<path d="M313.7 238.8l-.2 .2z"/>
<path d="M313 239h.5z"/>
<path d="M312.7 238.8l.3 .2z"/>
<path d="M314.2 237.5h1z"/>
<path d="M314.2 237.5v1.5z"/>
<path d="M314.2 239h1z"/>
<path d="M314.2 238.2h.5z"/>
<path d="M315.7 237.5v1.5z"/>
<path d="M315.7 239h.8z"/>
<path d="M316.5 239l.2-.2z"/>
<path d="M316.7 237.7v1.1z"/>
<path d="M316.5 237.5l.2 .2z"/>
<path d="M315.7 237.5h.8z"/>
<path d="M319 237.5h.5z"/>
<path d="M318.7 237.7l.3-.2z"/>
<path d="M318.7 237.7v1.1z"/>
<path d="M318.7 238.8l.3 .2z"/>
<path d="M319 239h.5z"/>
<path d="M319.5 239l.2-.2z"/>
<path d="M319.7 237.7v1.1z"/>
<path d="M319.5 237.5l.2 .2z"/>
<path d="M320.2 237.5v1.5z"/>
<path d="M320.2 237.5h.8z"/>
<path d="M321 237.5l.2 .2z"/>
<path d="M321.2 237.7v.5z"/>
<path d="M321 238.5l.2-.3z"/>
<path d="M320.2 238.5h.8z"/>
<path d="M320.7 238.5l.5 .5z"/>
<path d="M323.2 237.5v1.5z"/>
<path d="M323.2 237.5h.8z"/>
<path d="M324 237.5l.2 .2z"/>
<path d="M324.2 237.7v.5z"/>
<path d="M324.2 238.2l-.2 .3z"/>
<path d="M323.2 238.5h.8z"/>
<path d="M323.7 238.5l.5 .5z"/>
<path d="M324.7 237.5h1z"/>
<path d="M324.7 237.5v1.5z"/>
<path d="M324.7 239h1z"/>
<path d="M324.7 238.2h.5z"/>
<path d="M326.2 237.5v1.5z"/>
<path d="M326.2 237.5h.8z"/>
<path d="M327 237.5l.2 .2z"/>
<path d="M327.2 237.7v.5z"/>
<path d="M327.2 238.2l-.2 .3z"/>
<path d="M326.2 238.5h.8z"/>
<path d="M327.7 237.5v1.5z"/>
<path d="M327.7 237.5h.8z"/>
<path d="M328.5 237.5l.2 .2z"/>
<path d="M328.7 237.7v.5z"/>
<path d="M328.7 238.2l-.2 .3z"/>
<path d="M327.7 238.5h.8z"/>
<path d="M328.2 238.5l.5 .5z"/>
<path d="M329.5 237.5h.5z"/>
<path d="M329.2 237.7l.3-.2z"/>
<path d="M329.2 237.7v1.1z"/>
<path d="M329.2 238.8l.3 .2z"/>
<path d="M329.5 239h.5z"/>
<path d="M330 239l.2-.2z"/>
<path d="M330.2 237.7v1.1z"/>
<path d="M330 237.5l.2 .2z"/>
<path d="M330.7 237.5v1.5z"/>
<path d="M330.7 239h.7z"/>
<path d="M331.4 239l.3-.2z"/>
<path d="M331.7 237.7v1.1z"/>
<path d="M331.4 237.5l.3 .2z"/>
<path d="M330.7 237.5h.7z"/>
<path d="M332.2 237.5v1.3z"/>
<path d="M332.2 238.8l.3 .2z"/>
<path d="M332.5 239h.4z"/>
<path d="M332.9 239l.3-.2z"/>
<path d="M333.2 237.5v1.3z"/>
<path d="M334.4 237.5l.3 .2z"/>
<path d="M333.9 237.5h.5z"/>
<path d="M333.7 237.7l.2-.2z"/>
<path d="M333.7 237.7v1.1z"/>
<path d="M333.7 238.8l.2 .2z"/>
<path d="M333.9 239h.5z"/>
<path d="M334.4 239l.3-.2z"/>
<path d="M335.2 237.5h1z"/>
<path d="M335.2 237.5v1.5z"/>
<path d="M335.2 239h1z"/>
<path d="M335.2 238.2h.5z"/>
<path d="M336.7 237.5v1.5z"/>
<path d="M336.7 239h.7z"/>
<path d="M337.4 239l.3-.2z"/>
<path d="M337.7 237.7v1.1z"/>
<path d="M337.4 237.5l.3 .2z"/>
<path d="M336.7 237.5h.7z"/>
<path d="M339.9 237.5h.5z"/>
<path d="M339.7 237.7l.2-.2z"/>
<path d="M339.7 237.7v1.1z"/>
<path d="M339.7 238.8l.2 .2z"/>
<path d="M339.9 239h.5z"/>
<path d="M340.4 239l.3-.2z"/>
<path d="M340.7 237.7v1.1z"/>
<path d="M340.4 237.5l.3 .2z"/>
<path d="M341.2 237.5v1.5z"/>
<path d="M341.2 237.5h.7z"/>
<path d="M341.9 237.5l.3 .2z"/>
<path d="M342.2 237.7v.5z"/>
<path d="M342.2 238.2l-.3 .3z"/>
<path d="M341.2 238.5h.7z"/>
<path d="M341.7 238.5l.5 .5z"/>
<path d="M344.2 239h.5z"/>
<path d="M344.4 237.5v1.5z"/>
<path d="M344.2 237.5h.5z"/>
<path d="M345.7 237.5v1.5z"/>
<path d="M345.2 237.5h1z"/>
<path d="M346.9 237.3v.4z"/>
<path d="M346.9 237.7l-.2 .3z"/>
<path d="M348.2 237.5l.2 .2z"/>
<path d="M347.7 237.5h.5z"/>
<path d="M347.4 237.7l.3-.2z"/>
<path d="M347.4 237.7v.3z"/>
<path d="M347.4 238l.3 .2z"/>
<path d="M347.7 238.2h.5z"/>
<path d="M348.2 238.2l.2 .3z"/>
<path d="M348.4 238.5v.3z"/>
<path d="M348.4 238.8l-.2 .2z"/>
<path d="M347.7 239h.5z"/>
<path d="M347.4 238.8l.3 .2z"/>
<path d="M301.5 240l.2 .2z"/>
<path d="M301 240h.5z"/>
<path d="M301 240l-.2 .2z"/>
<path d="M300.8 240.2v1z"/>
<path d="M300.8 241.2l.2 .3z"/>
<path d="M301 241.5h.5z"/>
<path d="M301.5 241.5l.2-.3z"/>
<path d="M302.5 240h.5z"/>
<path d="M302.5 240l-.3 .2z"/>
<path d="M302.2 240.2v1z"/>
<path d="M302.2 241.2l.3 .3z"/>
<path d="M302.5 241.5h.5z"/>
<path d="M303 241.5l.2-.3z"/>
<path d="M303.2 240.2v1z"/>
<path d="M303 240l.2 .2z"/>
<path d="M303.7 240v1.5z"/>
<path d="M303.7 240l1.1 1.5z"/>
<path d="M304.8 240v1.5z"/>
<path d="M305.7 240v1.5z"/>
<path d="M305.2 240h1z"/>
<path d="M306.7 240h1z"/>
<path d="M306.7 240v1.5z"/>
<path d="M306.7 241.5h1z"/>
<path d="M306.7 240.7h.5z"/>
<path d="M308.2 240v1.5z"/>
<path d="M308.2 240l1 1.5z"/>
<path d="M309.2 240v1.5z"/>
<path d="M310.2 240v1.5z"/>
<path d="M309.7 240h1z"/>
<path d="M312.7 240v1.5z"/>
<path d="M312.7 241.5h.8z"/>
<path d="M313.5 241.5l.2-.3z"/>
<path d="M313.7 240.2v1z"/>
<path d="M313.5 240l.2 .2z"/>
<path d="M312.7 240h.8z"/>
<path d="M314.2 241.5h.5z"/>
<path d="M314.5 240v1.5z"/>
<path d="M314.2 240h.5z"/>
<path d="M316 240l.2 .2z"/>
<path d="M315.5 240h.5z"/>
<path d="M315.5 240l-.3 .2z"/>
<path d="M315.2 240.2v.3z"/>
<path d="M315.2 240.5l.3 .2z"/>
<path d="M315.5 240.7h.5z"/>
<path d="M316 240.7l.2 .3z"/>
<path d="M316.2 241v.2z"/>
<path d="M316.2 241.2l-.2 .3z"/>
<path d="M315.5 241.5h.5z"/>
<path d="M315.2 241.2l.3 .3z"/>
<path d="M317.5 240l.2 .2z"/>
<path d="M317 240h.5z"/>
<path d="M317 240l-.3 .2z"/>
<path d="M316.7 240.2v1z"/>
<path d="M316.7 241.2l.3 .3z"/>
<path d="M317 241.5h.5z"/>
<path d="M317.5 241.5l.2-.3z"/>
<path d="M318.2 240v1.5z"/>
<path d="M318.2 241.5h1z"/>
<path d="M320 240h.5z"/>
<path d="M319.7 240.2l.3-.2z"/>
<path d="M319.7 240.2v1z"/>
<path d="M319.7 241.2l.3 .3z"/>
<path d="M320 241.5h.5z"/>
<path d="M320.7 241.2l-.2 .3z"/>
<path d="M320.7 240.2v1z"/>
<path d="M320.5 240l.2 .2z"/>
<path d="M322 240l.2 .2z"/>
<path d="M321.5 240h.5z"/>
<path d="M321.5 240l-.3 .2z"/>
<path d="M321.2 240.2v.3z"/>
<path d="M321.2 240.5l.3 .2z"/>
<path d="M321.5 240.7h.5z"/>
<path d="M322 240.7l.2 .3z"/>
<path d="M322.2 241v.2z"/>
<path d="M322.2 241.2l-.2 .3z"/>
<path d="M321.5 241.5h.5z"/>
<path d="M321.2 241.2l.3 .3z"/>
<path d="M322.7 240h1z"/>
<path d="M322.7 240v1.5z"/>
<path d="M322.7 241.5h1z"/>
<path d="M322.7 240.7h.5z"/>
<path d="M324.2 240v1.5z"/>
<path d="M324.2 241.5h.8z"/>
<path d="M325 241.5l.2-.3z"/>
<path d="M325.2 240.2v1z"/>
<path d="M325 240l.2 .2z"/>
<path d="M324.2 240h.8z"/>
<path d="M327.2 241.5h.5z"/>
<path d="M327.5 240v1.5z"/>
<path d="M327.2 240h.5z"/>
<path d="M328.2 240v1.5z"/>
<path d="M328.2 240l1 1.5z"/>
<path d="M329.2 240v1.5z"/>
<path d="M331.2 240v1.5z"/>
<path d="M331.2 241.5l.5-.5z"/>
<path d="M331.7 241l.5 .5z"/>
<path d="M332.2 240v1.5z"/>
<path d="M332.7 240v1.5z"/>
<path d="M332.7 240.7h1z"/>
<path d="M333.7 240v1.5z"/>
<path d="M334.4 240h.6z"/>
<path d="M334.4 240l-.2 .2z"/>
<path d="M334.2 240.2v1z"/>
<path d="M334.2 241.2l.2 .3z"/>
<path d="M334.4 241.5h.6z"/>
<path d="M335.2 241.2l-.2 .3z"/>
<path d="M335.2 240.2v1z"/>
<path d="M335 240l.2 .2z"/>
<path d="M335.7 240v1.5z"/>
<path d="M335.7 241.5h1z"/>
<path d="M337.2 240h1z"/>
<path d="M337.2 240v1.5z"/>
<path d="M337.2 241.5h1z"/>
<path d="M337.2 240.7h.5z"/>
<path d="M340.4 240h.5z"/>
<path d="M340.4 240l-.2 .2z"/>
<path d="M340.2 240.2v1z"/>
<path d="M340.2 241.2l.2 .3z"/>
<path d="M340.4 241.5h.5z"/>
<path d="M341.2 241.2l-.3 .3z"/>
<path d="M341.2 240.2v1z"/>
<path d="M340.9 240l.3 .2z"/>
<path d="M341.7 240v1.5z"/>
<path d="M341.7 240h.7z"/>
<path d="M342.4 240l.3 .2z"/>
<path d="M342.7 240.2v.5z"/>
<path d="M342.7 240.7l-.3 .3z"/>
<path d="M341.7 241h.7z"/>
<path d="M342.2 241l.5 .5z"/>
<path d="M344.7 241.5h.5z"/>
<path d="M344.9 240v1.5z"/>
<path d="M344.7 240h.5z"/>
<path d="M345.7 240v1.5z"/>
<path d="M345.7 240l1 1.5z"/>
<path d="M346.7 240v1.5z"/>
<path d="M348.7 240v1.5z"/>
<path d="M348.7 240h.7z"/>
<path d="M349.4 240l.3 .2z"/>
<path d="M349.7 240.2v.5z"/>
<path d="M349.7 240.7l-.3 .3z"/>
<path d="M348.7 241h.7z"/>
<path d="M350.2 240.5v1z"/>
<path d="M350.7 240l-.5 .5z"/>
<path d="M350.7 240l.5 .5z"/>
<path d="M351.2 240.5v1z"/>
<path d="M350.2 240.7h1z"/>
<path d="M351.7 240v1.5z"/>
<path d="M351.7 240h.7z"/>
<path d="M352.4 240l.3 .2z"/>
<path d="M352.7 240.2v.5z"/>
<path d="M352.7 240.7l-.3 .3z"/>
<path d="M351.7 241h.7z"/>
<path d="M352.2 241l.5 .5z"/>
<path d="M353.7 240v1.5z"/>
<path d="M353.2 240h1z"/>
<path d="M300.8 242.4v1.5z"/>
<path d="M300.8 243.9l.4-.5z"/>
<path d="M301.2 243.4l.5 .5z"/>
<path d="M301.7 242.4v1.5z"/>
<path d="M302.2 243.9h.5z"/>
<path d="M302.5 242.4v1.5z"/>
<path d="M302.2 242.4h.5z"/>
<path d="M303.7 242.4v1.5z"/>
<path d="M303.2 242.4h1z"/>
<path d="M304.7 242.4v1.5z"/>
<path d="M304.7 243.2h1z"/>
<path d="M305.7 242.4v1.5z"/>
<path d="M306.5 242.4h.5z"/>
<path d="M306.5 242.4l-.3 .3z"/>
<path d="M306.2 242.7v1z"/>
<path d="M306.2 243.7l.3 .2z"/>
<path d="M306.5 243.9h.5z"/>
<path d="M307 243.9l.3-.2z"/>
<path d="M307.3 242.7v1z"/>
<path d="M307 242.4l.3 .3z"/>
<path d="M307.7 242.4v1.3z"/>
<path d="M307.7 243.7l.3 .2z"/>
<path d="M308 243.9h.5z"/>
<path d="M308.5 243.9l.2-.2z"/>
<path d="M308.7 242.4v1.3z"/>
<path d="M309.7 242.4v1.5z"/>
<path d="M309.2 242.4h1z"/>
<path d="M312.7 242.4v1.5z"/>
<path d="M312.2 242.4h1z"/>
<path d="M313.7 242.4v1.5z"/>
<path d="M313.7 243.2h1z"/>
<path d="M314.7 242.4v1.5z"/>
<path d="M315.2 242.4h1z"/>
<path d="M315.2 242.4v1.5z"/>
<path d="M315.2 243.9h1z"/>
<path d="M315.2 243.2h.5z"/>
<path d="M318.2 242.4v1.5z"/>
<path d="M318.2 242.4h.8z"/>
<path d="M319 242.4l.2 .3z"/>
<path d="M319.2 242.7v.5z"/>
<path d="M319.2 243.2l-.2 .2z"/>
<path d="M318.2 243.4h.8z"/>
<path d="M319.7 242.4v1.5z"/>
<path d="M319.7 242.4h.8z"/>
<path d="M320.5 242.4l.2 .3z"/>
<path d="M320.7 242.7v.5z"/>
<path d="M320.7 243.2l-.2 .2z"/>
<path d="M319.7 243.4h.8z"/>
<path d="M320.2 243.4l.5 .5z"/>
<path d="M321.2 243.9h.5z"/>
<path d="M321.5 242.4v1.5z"/>
<path d="M321.2 242.4h.5z"/>
<path d="M322.5 242.4h.5z"/>
<path d="M322.5 242.4l-.3 .3z"/>
<path d="M322.2 242.7v1z"/>
<path d="M322.2 243.7l.3 .2z"/>
<path d="M322.5 243.9h.5z"/>
<path d="M323 243.9l.2-.2z"/>
<path d="M323.2 242.7v1z"/>
<path d="M323 242.4l.2 .3z"/>
<path d="M323.7 242.4v1.5z"/>
<path d="M323.7 242.4h.8z"/>
<path d="M324.5 242.4l.2 .3z"/>
<path d="M324.7 242.7v.5z"/>
<path d="M324.7 243.2l-.2 .2z"/>
<path d="M323.7 243.4h.8z"/>
<path d="M324.2 243.4l.5 .5z"/>
<path d="M326.7 242.4v1.5z"/>
<path d="M326.7 243.9l.5-.5z"/>
<path d="M327.2 243.4l.5 .5z"/>
<path d="M327.7 242.4v1.5z"/>
<path d="M328.2 242.4v1.5z"/>
<path d="M328.2 242.4h.8z"/>
<path d="M329 242.4l.2 .3z"/>
<path d="M329.2 242.7v.5z"/>
<path d="M329.2 243.2l-.2 .2z"/>
<path d="M328.2 243.4h.8z"/>
<path d="M328.7 243.4l.5 .5z"/>
<path d="M329.7 243.9h.5z"/>
<path d="M330 242.4v1.5z"/>
<path d="M329.7 242.4h.5z"/>
<path d="M331.2 242.4v1.5z"/>
<path d="M330.7 242.4h1z"/>
<path d="M332.7 242.4v1.5z"/>
<path d="M332.2 242.4h1z"/>
<path d="M333.7 242.4h1z"/>
<path d="M333.7 242.4v1.5z"/>
<path d="M333.7 243.9h1z"/>
<path d="M333.7 243.2h.5z"/>
<path d="M335.2 242.4v1.5z"/>
<path d="M335.2 242.4l1 1.5z"/>
<path d="M336.2 242.4v1.5z"/>
<path d="M338.9 242.4l.3 .3z"/>
<path d="M338.4 242.4h.5z"/>
<path d="M338.4 242.4l-.2 .3z"/>
<path d="M338.2 242.7v1z"/>
<path d="M338.2 243.7l.2 .2z"/>
<path d="M338.4 243.9h.5z"/>
<path d="M338.9 243.9l.3-.2z"/>
<path d="M339.9 242.4h.5z"/>
<path d="M339.9 242.4l-.2 .3z"/>
<path d="M339.7 242.7v1z"/>
<path d="M339.7 243.7l.2 .2z"/>
<path d="M339.9 243.9h.5z"/>
<path d="M340.4 243.9l.3-.2z"/>
<path d="M340.7 242.7v1z"/>
<path d="M340.4 242.4l.3 .3z"/>
<path d="M341.2 242.4v1.5z"/>
<path d="M341.2 242.4l1 1.5z"/>
<path d="M342.2 242.4v1.5z"/>
<path d="M343.4 242.4l.3 .3z"/>
<path d="M342.9 242.4h.5z"/>
<path d="M342.9 242.4l-.2 .3z"/>
<path d="M342.7 242.7v.2z"/>
<path d="M342.7 242.9l.2 .3z"/>
<path d="M342.9 243.2h.5z"/>
<path d="M343.4 243.2l.3 .2z"/>
<path d="M343.7 243.4v.3z"/>
<path d="M343.7 243.7l-.3 .2z"/>
<path d="M342.9 243.9h.5z"/>
<path d="M342.7 243.7l.2 .2z"/>
<path d="M344.2 242.4h1z"/>
<path d="M344.2 242.4v1.5z"/>
<path d="M344.2 243.9h1z"/>
<path d="M344.2 243.2h.5z"/>
<path d="M345.7 242.4v1.5z"/>
<path d="M345.7 242.4l1 1.5z"/>
<path d="M346.7 242.4v1.5z"/>
<path d="M347.7 242.4v1.5z"/>
<path d="M347.2 242.4h1z"/>
<path d="M350.4 242.4h.5z"/>
<path d="M350.4 242.4l-.2 .3z"/>
<path d="M350.2 242.7v1z"/>
<path d="M350.2 243.7l.2 .2z"/>
<path d="M350.4 243.9h.5z"/>
<path d="M350.9 243.9l.3-.2z"/>
<path d="M351.2 242.7v1z"/>
<path d="M350.9 242.4l.3 .3z"/>
<path d="M351.7 242.4v1.5z"/>
<path d="M351.7 242.4h1z"/>
<path d="M351.7 243.2h.5z"/>
<path d="M300.8 244.9v1.5z"/>
<path d="M300.8 246.4h.7z"/>
<path d="M301.5 246.4l.2-.3z"/>
<path d="M301.7 245.1v1z"/>
<path d="M301.5 244.9l.2 .2z"/>
<path d="M300.8 244.9h.7z"/>
<path d="M302.2 245.4v1z"/>
<path d="M302.7 244.9l-.5 .5z"/>
<path d="M302.7 244.9l.5 .5z"/>
<path d="M303.2 245.4v1z"/>
<path d="M302.2 245.6h1z"/>
<path d="M303.7 244.9v1.5z"/>
<path d="M303.7 244.9l1.1 1.5z"/>
<path d="M304.8 244.9v1.5z"/>
<path d="M306.7 244.9v1.5z"/>
<path d="M306.7 245.9l1-1z"/>
<path d="M307 245.6l.7 .8z"/>
<path d="M308.2 246.4h.5z"/>
<path d="M308.5 244.9v1.5z"/>
<path d="M308.2 244.9h.5z"/>
<path d="M309.2 244.9v1.5z"/>
<path d="M309.2 244.9h.8z"/>
<path d="M310 244.9l.2 .2z"/>
<path d="M310.2 245.1v.5z"/>
<path d="M310.2 245.6l-.2 .3z"/>
<path d="M309.2 245.9h.8z"/>
<path d="M309.7 245.9l.5 .5z"/>
<path d="M310.7 244.9v1.5z"/>
<path d="M310.7 245.9l1-1z"/>
<path d="M311 245.6l.7 .8z"/>
<path d="M312.2 244.9v1.5z"/>
<path d="M312.2 244.9h.8z"/>
<path d="M313 244.9l.2 .2z"/>
<path d="M313.2 245.1v.5z"/>
<path d="M313.2 245.6l-.2 .3z"/>
<path d="M312.2 245.9h.8z"/>
<path d="M313.7 245.4v1z"/>
<path d="M313.7 245.4l.5-.5z"/>
<path d="M314.2 244.9l.5 .5z"/>
<path d="M314.7 245.4v1z"/>
<path d="M313.7 245.6h1z"/>
<path d="M315.7 244.9v1.5z"/>
<path d="M315.2 244.9h1z"/>
<path d="M316.7 244.9v1.5z"/>
<path d="M316.7 244.9h.8z"/>
<path d="M317.5 244.9l.2 .2z"/>
<path d="M317.7 245.1v.5z"/>
<path d="M317.7 245.6l-.2 .3z"/>
<path d="M316.7 245.9h.8z"/>
<path d="M317.2 245.9l.5 .5z"/>
<path d="M318.2 246.4h.5z"/>
<path d="M318.5 244.9v1.5z"/>
<path d="M318.2 244.9h.5z"/>
<path d="M320 244.9l.2 .2z"/>
<path d="M319.5 244.9h.5z"/>
<path d="M319.5 244.9l-.3 .2z"/>
<path d="M319.2 245.1v1z"/>
<path d="M319.2 246.1l.3 .3z"/>
<path d="M319.5 246.4h.5z"/>
<path d="M320 246.4l.2-.3z"/>
<path d="M320.7 244.9v1.5z"/>
<path d="M320.7 245.9l1-1z"/>
<path d="M321 245.6l.7 .8z"/>
<path d="M271.2 19.5v1.1z"/>
<path d="M271.2 19.5l.3-.3z"/>
<path d="M271.5 19.2h.5z"/>
<path d="M272 19.2l.3 .3z"/>
<path d="M272.3 19.5v1.1z"/>
<path d="M272 20.9l.3-.3z"/>
<path d="M271.5 20.9h.5z"/>
<path d="M271.2 20.6l.3 .3z"/>
<path d="M271.2 20.6l1.1-1.1z"/>
<path d="M272.9 19.5v1.1z"/>
<path d="M272.9 19.5l.3-.3z"/>
<path d="M273.2 19.2h.5z"/>
<path d="M273.7 19.2l.3 .3z"/>
<path d="M274 19.5v1.1z"/>
<path d="M274 20.6l-.3 .3z"/>
<path d="M273.2 20.9h.5z"/>
<path d="M272.9 20.6l.3 .3z"/>
<path d="M272.9 20.6l1.1-1.1z"/>
<path d="M274.6 19.8l.6-.6z"/>
<path d="M275.2 19.2v1.7z"/>
<path d="M274.6 20.9h1.1z"/>
<path d="M320.7 248.4v1.7z"/>
<path d="M320.7 250.1h.9z"/>
<path d="M321.6 250.1l.3-.3z"/>
<path d="M321.9 248.7v1.1z"/>
<path d="M321.6 248.4l.3 .3z"/>
<path d="M320.7 248.4h.9z"/>
<path d="M322.4 248.9v1.2z"/>
<path d="M322.4 248.9l.6-.5z"/>
<path d="M323 248.4l.5 .5z"/>
<path d="M323.5 248.9v1.2z"/>
<path d="M322.4 249.2h1.1z"/>
<path d="M324.1 248.4v1.7z"/>
<path d="M324.1 248.4l1.2 1.7z"/>
<path d="M325.3 248.4v1.7z"/>
<path d="M327.5 248.4v1.7z"/>
<path d="M327.5 249.5l1.2-1.1z"/>
<path d="M327.8 249.2l.9 .9z"/>
<path d="M329.2 250.1h.6z"/>
<path d="M329.5 248.4v1.7z"/>
<path d="M329.2 248.4h.6z"/>
<path d="M330.4 248.4v1.7z"/>
<path d="M330.4 248.4h.8z"/>
<path d="M331.2 248.4l.3 .3z"/>
<path d="M331.5 248.7v.5z"/>
<path d="M331.2 249.5l.3-.3z"/>
<path d="M330.4 249.5h.8z"/>
<path d="M330.9 249.5l.6 .6z"/>
<path d="M332.1 248.4v1.7z"/>
<path d="M332.1 249.5l1.1-1.1z"/>
<path d="M332.4 249.2l.8 .9z"/>
<path d="M333.8 248.4v1.7z"/>
<path d="M333.8 248.4h.8z"/>
<path d="M334.6 248.4l.3 .3z"/>
<path d="M334.9 248.7v.5z"/>
<path d="M334.9 249.2l-.3 .3z"/>
<path d="M333.8 249.5h.8z"/>
<path d="M335.5 248.9v1.2z"/>
<path d="M335.5 248.9l.5-.5z"/>
<path d="M336 248.4l.6 .5z"/>
<path d="M336.6 248.9v1.2z"/>
<path d="M335.5 249.2h1.1z"/>
<path d="M337.7 248.4v1.7z"/>
<path d="M337.2 248.4h1.1z"/>
<path d="M338.9 248.4v1.7z"/>
<path d="M338.9 248.4h.8z"/>
<path d="M339.7 248.4l.3 .3z"/>
<path d="M340 248.7v.5z"/>
<path d="M339.7 249.5l.3-.3z"/>
<path d="M338.9 249.5h.8z"/>
<path d="M339.4 249.5l.6 .6z"/>
<path d="M340.6 250.1h.5z"/>
<path d="M340.9 248.4v1.7z"/>
<path d="M340.6 248.4h.5z"/>
<path d="M342.6 248.4l.3 .3z"/>
<path d="M342 248.4h.6z"/>
<path d="M342 248.4l-.3 .3z"/>
<path d="M341.7 248.7v1.1z"/>
<path d="M341.7 249.8l.3 .3z"/>
<path d="M342 250.1h.6z"/>
<path d="M342.6 250.1l.3-.3z"/>
<path d="M343.4 248.4v1.7z"/>
<path d="M343.4 249.5l1.1-1.1z"/>
<path d="M343.7 249.2l.8 .9z"/>
<path d="M320.7 251.3v1.7z"/>
<path d="M320.7 253h.9z"/>
<path d="M321.9 252.7l-.3 .3z"/>
<path d="M321.9 251.6v1.1z"/>
<path d="M321.6 251.3l.3 .3z"/>
<path d="M320.7 251.3h.9z"/>
<path d="M322.4 251.9v1.1z"/>
<path d="M323 251.3l-.6 .6z"/>
<path d="M323 251.3l.5 .6z"/>
<path d="M323.5 251.9v1.1z"/>
<path d="M322.4 252.2h1.1z"/>
<path d="M324.1 251.3v1.7z"/>
<path d="M324.1 251.3l1.2 1.7z"/>
<path d="M325.3 251.3v1.7z"/>
<path d="M327.5 251.3v1.7z"/>
<path d="M327.5 252.5l1.2-1.2z"/>
<path d="M327.8 252.2l.9 .8z"/>
<path d="M329.2 253h.6z"/>
<path d="M329.5 251.3v1.7z"/>
<path d="M329.2 251.3h.6z"/>
<path d="M330.4 251.3v1.7z"/>
<path d="M330.4 251.3h.8z"/>
<path d="M331.2 251.3l.3 .3z"/>
<path d="M331.5 251.6v.6z"/>
<path d="M331.5 252.2l-.3 .3z"/>
<path d="M330.4 252.5h.8z"/>
<path d="M330.9 252.5l.6 .5z"/>
<path d="M332.1 251.3v1.7z"/>
<path d="M333.2 251.3l-1.1 1.2z"/>
<path d="M332.4 252.2l.8 .8z"/>
<path d="M333.8 251.3v1.7z"/>
<path d="M333.8 251.3h.8z"/>
<path d="M334.6 251.3l.3 .3z"/>
<path d="M334.9 251.6v.6z"/>
<path d="M334.9 252.2l-.3 .3z"/>
<path d="M333.8 252.5h.8z"/>
<path d="M335.5 251.9v1.1z"/>
<path d="M335.5 251.9l.5-.6z"/>
<path d="M336 251.3l.6 .6z"/>
<path d="M336.6 251.9v1.1z"/>
<path d="M335.5 252.2h1.1z"/>
<path d="M337.7 251.3v1.7z"/>
<path d="M337.2 251.3h1.1z"/>
<path d="M338.9 251.3v1.7z"/>
<path d="M338.9 251.3h.8z"/>
<path d="M339.7 251.3l.3 .3z"/>
<path d="M340 251.6v.6z"/>
<path d="M340 252.2l-.3 .3z"/>
<path d="M338.9 252.5h.8z"/>
<path d="M339.4 252.5l.6 .5z"/>
<path d="M340.6 253h.5z"/>
<path d="M340.9 251.3v1.7z"/>
<path d="M340.6 251.3h.5z"/>
<path d="M342.6 251.3l.3 .3z"/>
<path d="M342 251.3h.6z"/>
<path d="M342 251.3l-.3 .3z"/>
<path d="M341.7 251.6v1.1z"/>
<path d="M341.7 252.7l.3 .3z"/>
<path d="M342 253h.6z"/>
<path d="M342.6 253l.3-.3z"/>
<path d="M343.4 251.3v1.7z"/>
<path d="M343.4 252.5l1.1-1.2z"/>
<path d="M343.7 252.2l.8 .8z"/>
<path d="M320.7 254.5v1.7z"/>
<path d="M320.7 256.2h.9z"/>
<path d="M321.6 256.2l.3-.2z"/>
<path d="M321.9 254.8v1.2z"/>
<path d="M321.6 254.5l.3 .3z"/>
<path d="M320.7 254.5h.9z"/>
<path d="M322.4 255.1v1.1z"/>
<path d="M322.4 255.1l.6-.6z"/>
<path d="M323 254.5l.5 .6z"/>
<path d="M323.5 255.1v1.1z"/>
<path d="M322.4 255.4h1.1z"/>
<path d="M324.1 254.5v1.7z"/>
<path d="M324.1 254.5l1.2 1.7z"/>
<path d="M325.3 254.5v1.7z"/>
<path d="M327.5 254.5v1.7z"/>
<path d="M327.5 255.7l1.2-1.2z"/>
<path d="M327.8 255.4l.9 .8z"/>
<path d="M329.2 256.2h.6z"/>
<path d="M329.5 254.5v1.7z"/>
<path d="M329.2 254.5h.6z"/>
<path d="M330.4 254.5v1.7z"/>
<path d="M330.4 254.5h.8z"/>
<path d="M331.2 254.5l.3 .3z"/>
<path d="M331.5 254.8v.6z"/>
<path d="M331.2 255.7l.3-.3z"/>
<path d="M330.4 255.7h.8z"/>
<path d="M330.9 255.7l.6 .5z"/>
<path d="M332.1 254.5v1.7z"/>
<path d="M332.1 255.7l1.1-1.2z"/>
<path d="M332.4 255.4l.8 .8z"/>
<path d="M333.8 254.5v1.7z"/>
<path d="M333.8 254.5h.8z"/>
<path d="M334.6 254.5l.3 .3z"/>
<path d="M334.9 254.8v.6z"/>
<path d="M334.9 255.4l-.3 .3z"/>
<path d="M333.8 255.7h.8z"/>
<path d="M335.5 255.1v1.1z"/>
<path d="M335.5 255.1l.5-.6z"/>
<path d="M336 254.5l.6 .6z"/>
<path d="M336.6 255.1v1.1z"/>
<path d="M335.5 255.4h1.1z"/>
<path d="M337.7 254.5v1.7z"/>
<path d="M337.2 254.5h1.1z"/>
<path d="M338.9 254.5v1.7z"/>
<path d="M338.9 254.5h.8z"/>
<path d="M339.7 254.5l.3 .3z"/>
<path d="M340 254.8v.6z"/>
<path d="M339.7 255.7l.3-.3z"/>
<path d="M338.9 255.7h.8z"/>
<path d="M339.4 255.7l.6 .5z"/>
<path d="M340.6 256.2h.5z"/>
<path d="M340.9 254.5v1.7z"/>
<path d="M340.6 254.5h.5z"/>
<path d="M342.6 254.5l.3 .3z"/>
<path d="M342 254.5h.6z"/>
<path d="M342 254.5l-.3 .3z"/>
<path d="M341.7 254.8v1.2z"/>
<path d="M341.7 256l.3 .2z"/>
<path d="M342 256.2h.6z"/>
<path d="M342.6 256.2l.3-.2z"/>
<path d="M343.4 254.5v1.7z"/>
<path d="M343.4 255.7l1.1-1.2z"/>
<path d="M343.7 255.4l.8 .8z"/>
<path d="M159 198.4h2.4z"/>
<path d="M159 195.9h2.4z"/>
<path d="M159 193.5h2.4z"/>
<path d="M159 191h2.4z"/>
<path d="M159 188.5h2.4z"/>
<path d="M159 186.1h2.4z"/>
<path d="M329 77.7h2.5z"/>
<path d="M329 80.1h2.5z"/>
<path d="M329 82.6h2.5z"/>
<path d="M329 85h2.5z"/>
<path d="M329 87.5h2.5z"/>
<path d="M329 90h2.5z"/>
<path d="M329 94.9h2.5z"/>
<path d="M329 117.1h2.5z"/>
<path d="M329 92.4h2.5z"/>
<path d="M353.7 77.7h2.4z"/>
<path d="M329 102.3h2.5z"/>
<path d="M329 104.8h2.5z"/>
<path d="M329 107.2h2.5z"/>
<path d="M329 109.7h2.5z"/>
<path d="M329 112.2h2.5z"/>
<path d="M329 114.6h2.5z"/>
<path d="M329 99.8h2.5z"/>
<path d="M353.7 117.1h2.4z"/>
<path d="M353.7 114.6h2.4z"/>
<path d="M353.7 112.2h2.4z"/>
<path d="M353.7 109.7h2.4z"/>
<path d="M353.7 107.2h2.4z"/>
<path d="M353.7 104.8h2.4z"/>
<path d="M353.7 102.3h2.4z"/>
<path d="M353.7 99.8h2.4z"/>
<path d="M353.7 97.4h2.4z"/>
<path d="M353.7 94.9h2.4z"/>
<path d="M353.7 92.4h2.4z"/>
<path d="M353.7 90h2.4z"/>
<path d="M353.7 87.5h2.4z"/>
<path d="M353.7 85h2.4z"/>
<path d="M353.7 82.6h2.4z"/>
<path d="M353.7 80.1h2.4z"/>
<path d="M329 97.4h2.5z"/>
<path d="M284.7 193.5h2.4z"/>
<path d="M284.7 188.5h2.4z"/>
<path d="M284.7 191h2.4z"/>
<path d="M284.7 186.1h2.4z"/>
<path d="M151.6 203.3v2.5z"/>
<path d="M376.9 126.4v1.1z"/>
<path d="M376.9 126.4h.6z"/>
<path d="M377.5 126.4l.1 .2z"/>
<path d="M377.6 126.6v.3z"/>
<path d="M377.6 126.9l-.1 .2z"/>
<path d="M376.9 127.1h.6z"/>
<path d="M378 126.7v.8z"/>
<path d="M378.4 126.4l-.4 .3z"/>
<path d="M378.4 126.4l.4 .3z"/>
<path d="M378.8 126.7v.8z"/>
<path d="M378 126.9h.8z"/>
<path d="M379.7 126.4l.2 .2z"/>
<path d="M379.3 126.4h.4z"/>
<path d="M379.3 126.4l-.1 .2z"/>
<path d="M379.2 126.6v.7z"/>
<path d="M379.2 127.3l.1 .2z"/>
<path d="M379.3 127.5h.4z"/>
<path d="M379.7 127.5l.2-.2z"/>
<path d="M379.9 126.9v.4z"/>
<path d="M379.5 126.9h.4z"/>
<path d="M380.3 126.4h.8z"/>
<path d="M380.3 126.4v1.1z"/>
<path d="M380.3 127.5h.8z"/>
<path d="M380.3 126.9h.4z"/>
<path d="M381.4 127.5h.8z"/>
<path d="M382.2 126.7l-.8 .8z"/>
<path d="M382.2 126.6v.1z"/>
<path d="M382 126.4l.2 .2z"/>
<path d="M381.6 126.4h.4z"/>
<path d="M381.6 126.4l-.2 .2z"/>
<path d="M151.6 178.7v2.4z"/>
<path d="M119.5 188.5v2.5z"/>
<path d="M119.5 193.5v2.4z"/>
<path d="M119.5 191v.5z"/>
<path d="M119.5 193v.5z"/>
<path d="M131.9 188.5v2.5z"/>
<path d="M131.9 193.5v2.4z"/>
<path d="M131.9 191v.5z"/>
<path d="M131.9 193v.5z"/>
<path d="M107.2 188.5v2.5z"/>
<path d="M107.2 193.5v2.4z"/>
<path d="M107.2 191v.5z"/>
<path d="M107.2 193v.5z"/>
<path d="M107.2 203.3v2.5z"/>
<path d="M161.4 45.6v2.5z"/>
<path d="M156.5 139.3v2.4z"/>
<path d="M260 178.7v2.4z"/>
<path d="M264.9 203.3v2.5z"/>
<path d="M250.2 188.5h2.4z"/>
<path d="M250.2 191h2.4z"/>
<path d="M250.2 193.5h2.4z"/>
<path d="M250.2 195.9h2.4z"/>
<path d="M250.2 198.4h2.4z"/>
<path d="M250.2 186.1h2.4z"/>
<path d="M279.7 45.6v2.5z"/>
<path d="M279.7 80.1v2.5z"/>
<path d="M247.7 50.5v2.5z"/>
<path d="M247.7 57.9v2.5z"/>
<path d="M246.7 57.6l1 .3z"/>
<path d="M246.7 57.6l2-.6z"/>
<path d="M246.7 56.3l2 .7z"/>
<path d="M246.7 56.3l2-.6z"/>
<path d="M246.7 55.1l2 .6z"/>
<path d="M246.7 55.1l2-.6z"/>
<path d="M246.7 53.9l2 .6z"/>
<path d="M246.7 53.9l2-.6z"/>
<path d="M247.7 53l1 .3z"/>
<path d="M247.7 45.6v2.5z"/>
<path d="M252.6 62.9h2.5z"/>
<path d="M272.3 70.3h2.5z"/>
<path d="M272.3 62.9h2.5z"/>
<path d="M272.3 67.8h2.5z"/>
<path d="M40.7 87.5h2.4z"/>
<path d="M40.7 90h2.4z"/>
<path d="M40.7 92.4h2.4z"/>
<path d="M40.7 94.9h2.4z"/>
<path d="M40.7 97.4h2.4z"/>
<path d="M40.7 99.8h2.4z"/>
<path d="M40.7 102.3h2.4z"/>
<path d="M40.7 104.8h2.4z"/>
<path d="M40.7 107.2h2.4z"/>
<path d="M114.6 134.3v2.5z"/>
<path d="M114.6 141.7v2.5z"/>
<path d="M113.6 141.3l1 .4z"/>
<path d="M113.6 141.3l2-.6z"/>
<path d="M113.6 140.1l2 .6z"/>
<path d="M113.6 140.1l2-.6z"/>
<path d="M113.6 138.9l2 .6z"/>
<path d="M113.6 138.9l2-.6z"/>
<path d="M113.6 137.7l2 .6z"/>
<path d="M113.6 137.7l2-.7z"/>
<path d="M114.6 136.8l1 .2z"/>
<path d="M114.6 149.1v2.5z"/>
<path d="M297 50.5v2.5z"/>
<path d="M297 55.5v2.4z"/>
<path d="M297 53v.5z"/>
<path d="M297 55v.5z"/>
<path d="M297 45.6v2.5z"/>
<path d="M297 60.4v2.5z"/>
<path d="M225.5 60.4v2.5z"/>
<path d="M225.5 67.8v2.5z"/>
<path d="M224.5 67.4l1 .4z"/>
<path d="M224.5 67.4l2-.6z"/>
<path d="M224.5 66.2l2 .6z"/>
<path d="M224.5 66.2l2-.6z"/>
<path d="M224.5 65l2 .6z"/>
<path d="M224.5 65l2-.7z"/>
<path d="M224.5 63.7l2 .6z"/>
<path d="M224.5 63.7l2-.6z"/>
<path d="M225.5 62.9l1 .2z"/>
<path d="M215.7 60.4v2.5z"/>
<path d="M215.7 67.8v2.5z"/>
<path d="M214.7 67.4l1 .4z"/>
<path d="M214.7 67.4l1.9-.6z"/>
<path d="M214.7 66.2l1.9 .6z"/>
<path d="M214.7 66.2l1.9-.6z"/>
<path d="M214.7 65l1.9 .6z"/>
<path d="M214.7 65l1.9-.7z"/>
<path d="M214.7 63.7l1.9 .6z"/>
<path d="M214.7 63.7l1.9-.6z"/>
<path d="M215.7 62.9l.9 .2z"/>
<path d="M205.8 60.4v2.5z"/>
<path d="M205.8 67.8v2.5z"/>
<path d="M204.8 67.4l1 .4z"/>
<path d="M204.8 67.4l2-.6z"/>
<path d="M204.8 66.2l2 .6z"/>
<path d="M204.8 66.2l2-.6z"/>
<path d="M204.8 65l2 .6z"/>
<path d="M204.8 65l2-.7z"/>
<path d="M204.8 63.7l2 .6z"/>
<path d="M204.8 63.7l2-.6z"/>
<path d="M205.8 62.9l1 .2z"/>
<path d="M195.9 60.4v2.5z"/>
<path d="M195.9 67.8v2.5z"/>
<path d="M195 67.4l.9 .4z"/>
<path d="M195 67.4l1.9-.6z"/>
<path d="M195 66.2l1.9 .6z"/>
<path d="M195 66.2l1.9-.6z"/>
<path d="M195 65l1.9 .6z"/>
<path d="M195 65l1.9-.7z"/>
<path d="M195 63.7l1.9 .6z"/>
<path d="M195 63.7l1.9-.6z"/>
<path d="M195.9 62.9l1 .2z"/>
<path d="M186.1 60.4v2.5z"/>
<path d="M186.1 67.8v2.5z"/>
<path d="M185.1 67.4l1 .4z"/>
<path d="M185.1 67.4l2-.6z"/>
<path d="M185.1 66.2l2 .6z"/>
<path d="M185.1 66.2l2-.6z"/>
<path d="M185.1 65l2 .6z"/>
<path d="M185.1 65l2-.7z"/>
<path d="M185.1 63.7l2 .6z"/>
<path d="M185.1 63.7l2-.6z"/>
<path d="M186.1 62.9l1 .2z"/>
<path d="M107.2 178.7v2.4z"/>
<path d="M186.1 45.6v2.5z"/>
<path d="M117.1 57.9h2.4z"/>
<path d="M117.1 60.4h2.4z"/>
<path d="M117.1 62.9h2.4z"/>
<path d="M139.3 57.9h2.4z"/>
<path d="M139.3 60.4h2.4z"/>
<path d="M139.3 62.9h2.4z"/>
<path d="M117.1 75.2h2.4z"/>
<path d="M117.1 77.7h2.4z"/>
<path d="M117.1 80.1h2.4z"/>
<path d="M139.3 75.2h2.4z"/>
<path d="M139.3 77.7h2.4z"/>
<path d="M139.3 80.1h2.4z"/>
<path d="M117.1 92.4h2.4z"/>
<path d="M117.1 94.9h2.4z"/>
<path d="M117.1 97.4h2.4z"/>
<path d="M139.3 92.4h2.4z"/>
<path d="M139.3 94.9h2.4z"/>
<path d="M139.3 97.4h2.4z"/>
<path d="M117.1 109.7h2.4z"/>
<path d="M117.1 112.2h2.4z"/>
<path d="M117.1 114.6h2.4z"/>
<path d="M139.3 109.7h2.4z"/>
<path d="M139.3 112.2h2.4z"/>
<path d="M139.3 114.6h2.4z"/>
<path d="M117.1 126.9h2.4z"/>
<path d="M117.1 129.4h2.4z"/>
<path d="M117.1 131.9h2.4z"/>
<path d="M139.3 126.9h2.4z"/>
<path d="M139.3 129.4h2.4z"/>
<path d="M139.3 131.9h2.4z"/>
<path d="M102.3 57.9h2.5z"/>
<path d="M94.9 57.9h2.5z"/>
<path d="M97.7 57l-.3 .9z"/>
<path d="M97.7 57l.6 1.9z"/>
<path d="M99 57l-.7 1.9z"/>
<path d="M99 57l.6 1.9z"/>
<path d="M100.2 57l-.6 1.9z"/>
<path d="M100.2 57l.6 1.9z"/>
<path d="M101.4 57l-.6 1.9z"/>
<path d="M101.4 57l.6 1.9z"/>
<path d="M102.3 57.9l-.3 1z"/>
<path d="M102.3 75.2h2.5z"/>
<path d="M94.9 75.2h2.5z"/>
<path d="M97.7 74.2l-.3 1z"/>
<path d="M97.7 74.2l.6 2z"/>
<path d="M99 74.2l-.7 2z"/>
<path d="M99 74.2l.6 2z"/>
<path d="M100.2 74.2l-.6 2z"/>
<path d="M100.2 74.2l.6 2z"/>
<path d="M101.4 74.2l-.6 2z"/>
<path d="M101.4 74.2l.6 2z"/>
<path d="M102.3 75.2l-.3 1z"/>
<path d="M102.3 92.4h2.5z"/>
<path d="M94.9 92.4h2.5z"/>
<path d="M97.7 91.5l-.3 .9z"/>
<path d="M97.7 91.5l.6 1.9z"/>
<path d="M99 91.5l-.7 1.9z"/>
<path d="M99 91.5l.6 1.9z"/>
<path d="M100.2 91.5l-.6 1.9z"/>
<path d="M100.2 91.5l.6 1.9z"/>
<path d="M101.4 91.5l-.6 1.9z"/>
<path d="M101.4 91.5l.6 1.9z"/>
<path d="M102.3 92.4l-.3 1z"/>
<path d="M102.3 109.7h2.5z"/>
<path d="M94.9 109.7h2.5z"/>
<path d="M97.7 108.7l-.3 1z"/>
<path d="M97.7 108.7l.6 2z"/>
<path d="M99 108.7l-.7 2z"/>
<path d="M99 108.7l.6 2z"/>
<path d="M100.2 108.7l-.6 2z"/>
<path d="M100.2 108.7l.6 2z"/>
<path d="M101.4 108.7l-.6 2z"/>
<path d="M101.4 108.7l.6 2z"/>
<path d="M102.3 109.7l-.3 1z"/>
<path d="M102.3 126.9h2.5z"/>
<path d="M94.9 126.9h2.5z"/>
<path d="M97.7 126l-.3 .9z"/>
<path d="M97.7 126l.6 1.9z"/>
<path d="M99 126l-.7 1.9z"/>
<path d="M99 126l.6 1.9z"/>
<path d="M100.2 126l-.6 1.9z"/>
<path d="M100.2 126l.6 1.9z"/>
<path d="M101.4 126l-.6 1.9z"/>
<path d="M101.4 126l.6 1.9z"/>
<path d="M102.3 126.9l-.3 1z"/>
<path d="M385.7 107.2v2.5z"/>
<path d="M385.7 80.1v2.5z"/>
<path d="M385.7 87.5v2.5z"/>
<path d="M384.7 87.1l1 .4z"/>
<path d="M384.7 87.1l2-.6z"/>
<path d="M384.7 85.9l2 .6z"/>
<path d="M384.7 85.9l2-.6z"/>
<path d="M384.7 84.7l2 .6z"/>
<path d="M384.7 84.7l2-.6z"/>
<path d="M384.7 83.4l2 .7z"/>
<path d="M384.7 83.4l2-.6z"/>
<path d="M385.7 82.6l1 .2z"/>
<path d="M385.7 102.3v2.5z"/>
<path d="M385.7 97.4v2.4z"/>
<path d="M385.7 99.8v2.5z"/>
<path d="M383.7 100.6l-1.3 1.3z"/>
<path d="M382.5 103l1.4-1.3z"/>
<path d="M382.8 101.1l-.4 .8z"/>
<path d="M382.8 101.1l.4 .5z"/>
<path d="M382.4 101.9l.8-.3z"/>
<path d="M382.5 101.8h.2z"/>
<path d="M382.5 101.7h.5z"/>
<path d="M382.5 101.5h.7z"/>
<path d="M382.6 101.4h.5z"/>
<path d="M382.6 101.3h.4z"/>
<path d="M382.7 101.2h.2z"/>
<path d="M382.9 102.2l-.4 .8z"/>
<path d="M382.9 102.2l.5 .5z"/>
<path d="M382.5 103l.9-.3z"/>
<path d="M382.6 102.9h.2z"/>
<path d="M382.6 102.8h.4z"/>
<path d="M382.6 102.7h.7z"/>
<path d="M382.7 102.6h.6z"/>
<path d="M382.8 102.5h.4z"/>
<path d="M382.8 102.4h.3z"/>
</g>
<g fill="#800000" stroke="#800000" stroke-width=".25">
<path d="M18.5 260h49.3z"/>
<path d="M67.8 260h49.3z"/>
<path d="M117.1 260h49.3z"/>
<path d="M166.4 260h49.3z"/>
<path d="M215.7 260h49.2z"/>
<path d="M264.9 260h34.6z"/>
<path d="M314.2 260h49.3z"/>
<path d="M363.5 260h49.3z"/>
<path d="M412.8 210.7v20.4z"/>
<path d="M412.8 161.4v49.3z"/>
<path d="M412.8 112.2v49.2z"/>
<path d="M412.8 62.9v49.3z"/>
<path d="M412.8 21.6v41.3z"/>
<path d="M412.8 18.5v3.1z"/>
<path d="M412.8 13.6v4.9z"/>
<path d="M67.8 260v4.9z"/>
<path d="M117.1 260v4.9z"/>
<path d="M166.4 260v4.9z"/>
<path d="M215.7 260v4.9z"/>
<path d="M264.9 260v4.9z"/>
<path d="M314.2 260v4.9z"/>
<path d="M363.5 260v4.9z"/>
<path d="M412.8 210.7h5z"/>
<path d="M412.8 161.4h5z"/>
<path d="M412.8 112.2h5z"/>
<path d="M412.8 62.9h5z"/>
<path d="M18.5 210.7v49.3z"/>
<path d="M18.5 161.4v49.3z"/>
<path d="M18.5 112.2v49.2z"/>
<path d="M18.5 62.9v49.3z"/>
<path d="M18.5 13.6v49.3z"/>
<path d="M13.6 210.7h4.9z"/>
<path d="M13.6 161.4h4.9z"/>
<path d="M13.6 112.2h4.9z"/>
<path d="M13.6 62.9h4.9z"/>
<path d="M18.5 13.6h49.3z"/>
<path d="M67.8 13.6h49.3z"/>
<path d="M117.1 13.6h49.3z"/>
<path d="M166.4 13.6h49.3z"/>
<path d="M215.7 13.6h49.2z"/>
<path d="M264.9 13.6h5z"/>
<path d="M269.9 13.6h7.4z"/>
<path d="M277.3 13.6h36.9z"/>
<path d="M314.2 13.6h44.4z"/>
<path d="M358.6 13.6h4.9z"/>
<path d="M363.5 13.6h15.4z"/>
<path d="M378.9 13.6h33.9z"/>
<path d="M67.8 8.7v4.9z"/>
<path d="M117.1 8.7v4.9z"/>
<path d="M166.4 8.7v4.9z"/>
<path d="M215.7 8.7v4.9z"/>
<path d="M264.9 8.7v4.9z"/>
<path d="M314.2 8.7v4.9z"/>
<path d="M363.5 8.7v4.9z"/>
<path d="M378.9 13.6v4.9z"/>
<path d="M378.9 18.5h33.9z"/>
<path d="M358.6 18.5h20.3z"/>
<path d="M277.3 18.5h81.3z"/>
<path d="M269.9 18.5h7.4z"/>
<path d="M269.9 18.5v3.1z"/>
<path d="M269.9 21.6h7.4z"/>
<path d="M277.3 21.6h81.3z"/>
<path d="M358.6 21.6h20.3z"/>
<path d="M378.9 21.6h33.9z"/>
<path d="M277.3 18.5v3.1z"/>
<path d="M358.6 18.5v3.1z"/>
<path d="M378.9 18.5v3.1z"/>
<path d="M269.9 13.6v4.9z"/>
<path d="M277.3 13.6v4.9z"/>
<path d="M358.6 13.6v4.9z"/>
<path d="M299.5 231.1v16.6z"/>
<path d="M299.5 247.7h48z"/>
<path d="M355.5 231.1v16.6z"/>
<path d="M299.5 231.1h56z"/>
<path d="M355.5 231.1h57.3z"/>
<path d="M412.8 231.1v16.6z"/>
<path d="M355.5 247.7h57.3z"/>
<path d="M347.5 247.7h8z"/>
<path d="M299.5 247.7v3.1z"/>
<path d="M299.5 250.8h48z"/>
<path d="M347.5 247.7v3.1z"/>
<path d="M299.5 250.8v3z"/>
<path d="M299.5 253.8h48z"/>
<path d="M347.5 250.8v3z"/>
<path d="M299.5 253.8v3.1z"/>
<path d="M299.5 256.9h48z"/>
<path d="M347.5 253.8v3.1z"/>
<path d="M412.8 247.7v6.1z"/>
<path d="M347.5 253.8h65.3z"/>
<path d="M347.5 256.9h65.3z"/>
<path d="M412.8 253.8v3.1z"/>
<path d="M299.5 256.9v3.1z"/>
<path d="M299.5 260h14.7z"/>
<path d="M412.8 256.9v3.1z"/>
<path d="M161.4 183.6h12.4z"/>
<path d="M173.8 183.6v17.3z"/>
<path d="M161.4 200.9h12.4z"/>
<path d="M161.4 183.6v17.3z"/>
<path d="M331.5 75.2h22.2z"/>
<path d="M353.7 75.2v44.3z"/>
<path d="M331.5 119.5h22.2z"/>
<path d="M331.5 75.2v44.3z"/>
<path d="M287.1 183.6h9.9z"/>
<path d="M297 183.6v12.3z"/>
<path d="M287.1 195.9h9.9z"/>
<path d="M287.1 183.6v12.3z"/>
<path d="M149.7 205.8h3.7z"/>
<path d="M375.9 126.9l1.2-1.2z"/>
<path d="M377.1 125.7h7.1z"/>
<path d="M384.2 125.7h.2z"/>
<path d="M384.2 128.2h.2z"/>
<path d="M377.1 128.2h7.1z"/>
<path d="M375.9 126.9l1.2 1.3z"/>
<path d="M384.5 125.7l1.2 1.2z"/>
<path d="M384.5 128.2l1.2-1.3z"/>
<path d="M384.2 125.7h.3z"/>
<path d="M384.2 128.2h.3z"/>
<path d="M151.6 178.7l1.2 1.8z"/>
<path d="M151.6 178.7l-1.3 1.8z"/>
<path d="M105.4 205.8h3.7z"/>
<path d="M161.4 45.6l1.3 1.9z"/>
<path d="M161.4 45.6l-1.2 1.9z"/>
<path d="M154.7 141.7h3.7z"/>
<path d="M260 178.7l1.3 1.8z"/>
<path d="M260 178.7l-1.2 1.8z"/>
<path d="M263.1 205.8h3.7z"/>
<path d="M240.3 200.9h9.9z"/>
<path d="M250.2 183.6v17.3z"/>
<path d="M240.3 183.6h9.9z"/>
<path d="M240.3 183.6v17.3z"/>
<path d="M279.7 45.6l1.3 1.9z"/>
<path d="M279.7 45.6l-1.2 1.9z"/>
<path d="M277.9 82.6h3.7z"/>
<path d="M247.7 45.6l1.2 1.9z"/>
<path d="M247.7 45.6l-1.2 1.9z"/>
<path d="M255.1 60.4v12.3z"/>
<path d="M255.1 72.7h17.2z"/>
<path d="M272.3 60.4v12.3z"/>
<path d="M255.1 60.4h17.2z"/>
<path d="M35.7 85h5z"/>
<path d="M35.7 85v24.7z"/>
<path d="M35.7 109.7h5z"/>
<path d="M40.7 85v24.7z"/>
<path d="M112.8 151.6h3.7z"/>
<path d="M297 45.6l1.2 1.9z"/>
<path d="M297 45.6l-1.2 1.9z"/>
<path d="M295.1 62.9h3.7z"/>
<path d="M107.2 178.7l1.3 1.8z"/>
<path d="M107.2 178.7l-1.2 1.8z"/>
<path d="M186.1 45.6l1.2 1.9z"/>
<path d="M186.1 45.6l-1.3 1.9z"/>
<path d="M119.5 55.5v9.8z"/>
<path d="M119.5 65.3h19.8z"/>
<path d="M139.3 55.5v9.8z"/>
<path d="M119.5 55.5h19.8z"/>
<path d="M119.5 72.7v9.9z"/>
<path d="M119.5 82.6h19.8z"/>
<path d="M139.3 72.7v9.9z"/>
<path d="M119.5 72.7h19.8z"/>
<path d="M119.5 90v9.8z"/>
<path d="M119.5 99.8h19.8z"/>
<path d="M139.3 90v9.8z"/>
<path d="M119.5 90h19.8z"/>
<path d="M119.5 107.2v9.9z"/>
<path d="M119.5 117.1h19.8z"/>
<path d="M139.3 107.2v9.9z"/>
<path d="M119.5 107.2h19.8z"/>
<path d="M119.5 124.5v9.8z"/>
<path d="M119.5 134.3h19.8z"/>
<path d="M139.3 124.5v9.8z"/>
<path d="M119.5 124.5h19.8z"/>
<path d="M383.9 109.7h3.7z"/>
<path d="M386.9 99.8l-1.2 2.5z"/>
<path d="M384.5 99.8l1.2 2.5z"/>
<path d="M385.7 102.3h1.2z"/>
<path d="M384.5 102.3h1.2z"/>
<path d="M385.7 99.8h1.2z"/>
<path d="M384.5 99.8h1.2z"/>
</g>
<g fill="#800000" stroke="#800000" stroke-width=".3">
<path d="M348.9 250.2v2.3z"/>
<path d="M348.9 250.2h.6z"/>
<path d="M349.5 250.2l.5 .6z"/>
<path d="M350 250.8v1.7z"/>
<path d="M350 250.8l.6-.6z"/>
<path d="M350.6 250.2l.5 .6z"/>
<path d="M351.1 250.8v1.7z"/>
<path d="M352.9 252.5h1.1z"/>
<path d="M354.6 251.9l-.6 .6z"/>
<path d="M354.6 250.8v1.1z"/>
<path d="M354 250.2l.6 .6z"/>
<path d="M352.9 250.2h1.1z"/>
<path d="M352.3 250.8l.6-.6z"/>
<path d="M352.3 250.8v1.1z"/>
<path d="M352.3 251.9l.6 .6z"/>
<path d="M356.3 249.6v2.3z"/>
<path d="M356.3 251.9l.5 .6z"/>
<path d="M355.7 250.2h1.1z"/>
<path d="M358.5 252.5h1.2z"/>
<path d="M360.2 251.9l-.5 .6z"/>
<path d="M360.2 250.8v1.1z"/>
<path d="M359.7 250.2l.5 .6z"/>
<path d="M358.5 250.2h1.2z"/>
<path d="M358 250.8l.5-.6z"/>
<path d="M358 250.8v1.1z"/>
<path d="M358 251.9l.5 .6z"/>
<path d="M361.4 250.2v2.3z"/>
<path d="M361.4 251.3l1.1-1.1z"/>
<path d="M362.5 250.2h.6z"/>
<path d="M365.9 249.1l.6 .5z"/>
<path d="M364.8 249.1h1.1z"/>
<path d="M364.8 249.1l-.6 .5z"/>
<path d="M364.2 249.6v2.3z"/>
<path d="M364.2 251.9l.6 .6z"/>
<path d="M364.8 252.5h1.1z"/>
<path d="M365.9 252.5l.6-.6z"/>
<path d="M368.2 252.5h1.1z"/>
<path d="M369.3 252.5l.6-.6z"/>
<path d="M369.9 250.8v1.1z"/>
<path d="M369.3 250.2l.6 .6z"/>
<path d="M368.2 250.2h1.1z"/>
<path d="M367.6 250.8l.6-.6z"/>
<path d="M367.6 250.8v1.1z"/>
<path d="M367.6 251.9l.6 .6z"/>
<path d="M371 250.2v2.3z"/>
<path d="M371 250.2h1.7z"/>
<path d="M372.7 250.2l.6 .6z"/>
<path d="M373.3 250.8v1.7z"/>
<path d="M375 249.6v2.3z"/>
<path d="M375 251.9l.6 .6z"/>
<path d="M374.4 250.2h1.2z"/>
<path d="M376.7 250.2v2.3z"/>
<path d="M376.7 251.3l1.1-1.1z"/>
<path d="M377.8 250.2h.6z"/>
<path d="M380.1 252.5h1.1z"/>
<path d="M381.2 252.5l.6-.6z"/>
<path d="M381.8 250.8v1.1z"/>
<path d="M381.2 250.2l.6 .6z"/>
<path d="M380.1 250.2h1.1z"/>
<path d="M380.1 250.2l-.6 .6z"/>
<path d="M379.5 250.8v1.1z"/>
<path d="M379.5 251.9l.6 .6z"/>
<path d="M382.9 249.1h.6z"/>
<path d="M383.5 249.1v3.4z"/>
<path d="M382.9 252.5h1.2z"/>
<path d="M385.2 249.1h.6z"/>
<path d="M385.8 249.1v3.4z"/>
<path d="M385.2 252.5h1.1z"/>
<path d="M388 252.5h1.2z"/>
<path d="M387.5 251.9l.5 .6z"/>
<path d="M387.5 250.8v1.1z"/>
<path d="M387.5 250.8l.5-.6z"/>
<path d="M388 250.2h1.2z"/>
<path d="M389.2 250.2l.5 .6z"/>
<path d="M389.7 250.8v.5z"/>
<path d="M387.5 251.3h2.2z"/>
<path d="M390.9 250.2v2.3z"/>
<path d="M392 250.2l-1.1 1.1z"/>
<path d="M392 250.2h.6z"/>
<path d="M361.2 235.4v2.3z"/>
<path d="M361.2 235.4l1.1-1.1z"/>
<path d="M362.3 234.3l1.2 1.1z"/>
<path d="M363.5 235.4v2.3z"/>
<path d="M361.2 236h2.3z"/>
<path d="M364.6 235.4v1.7z"/>
<path d="M364.6 237.1l.6 .6z"/>
<path d="M365.2 237.7h1.7z"/>
<path d="M366.9 235.4v2.3z"/>
<path d="M368.6 234.8v2.3z"/>
<path d="M368.6 237.1l.6 .6z"/>
<path d="M368 235.4h1.2z"/>
<path d="M370.9 237.7h1.1z"/>
<path d="M372 237.7l.6-.6z"/>
<path d="M372.6 236v1.1z"/>
<path d="M372 235.4l.6 .6z"/>
<path d="M370.9 235.4h1.1z"/>
<path d="M370.9 235.4l-.6 .6z"/>
<path d="M370.3 236v1.1z"/>
<path d="M370.3 237.1l.6 .6z"/>
<path d="M373.7 235.4v2.3z"/>
<path d="M373.7 235.4h1.7z"/>
<path d="M375.4 235.4l.6 .6z"/>
<path d="M376 236v1.7z"/>
<path d="M377.7 237.7h1.1z"/>
<path d="M378.8 237.7l.6-.6z"/>
<path d="M379.4 236v1.1z"/>
<path d="M378.8 235.4l.6 .6z"/>
<path d="M377.7 235.4h1.1z"/>
<path d="M377.7 235.4l-.6 .6z"/>
<path d="M377.1 236v1.1z"/>
<path d="M377.1 237.1l.6 .6z"/>
<path d="M380.5 235.4v2.3z"/>
<path d="M380.5 235.4h.6z"/>
<path d="M381.1 235.4l.5 .6z"/>
<path d="M381.6 236v1.7z"/>
<path d="M381.6 236l.6-.6z"/>
<path d="M382.2 235.4l.6 .6z"/>
<path d="M382.8 236v1.7z"/>
<path d="M384.5 237.7h1.1z"/>
<path d="M385.6 237.7l.6-.6z"/>
<path d="M386.2 236v1.1z"/>
<path d="M385.6 235.4l.6 .6z"/>
<path d="M384.5 235.4h1.1z"/>
<path d="M384.5 235.4l-.6 .6z"/>
<path d="M383.9 236v1.1z"/>
<path d="M383.9 237.1l.6 .6z"/>
<path d="M387.3 235.4v1.7z"/>
<path d="M387.3 237.1l.6 .6z"/>
<path d="M387.9 237.7h1.7z"/>
<path d="M389.6 235.4v2.3z"/>
<path d="M390.7 237.7h1.7z"/>
<path d="M392.4 237.7l.6-.6z"/>
<path d="M392.4 236.6l.6 .5z"/>
<path d="M391.3 236.6h1.1z"/>
<path d="M390.7 236l.6 .6z"/>
<path d="M391.3 235.4l-.6 .6z"/>
<path d="M391.3 235.4h1.7z"/>
<path d="M362.5 241.1v3.3z"/>
<path d="M362.5 241.1h2.2z"/>
<path d="M362.5 242.8h1.1z"/>
<path d="M365.9 241.1h.5z"/>
<path d="M366.4 241.1v3.3z"/>
<path d="M365.9 244.4h1.1z"/>
<path d="M368.1 242.2v1.7z"/>
<path d="M368.1 243.9l.6 .5z"/>
<path d="M368.7 244.4h1.7z"/>
<path d="M370.4 242.2v2.8z"/>
<path d="M370.4 245l-.6 .6z"/>
<path d="M369.2 245.6h.6z"/>
<path d="M371.5 242.2h.6z"/>
<path d="M372.1 242.2v2.2z"/>
<path d="M371.5 244.4h1.2z"/>
<path d="M372.1 240.5v.6z"/>
<path d="M373.8 242.2v2.2z"/>
<path d="M373.8 242.2h1.7z"/>
<path d="M375.5 242.2l.6 .6z"/>
<path d="M376.1 242.8v1.6z"/>
<path d="M378.3 245.6h.6z"/>
<path d="M378.9 245.6l.6-.6z"/>
<path d="M379.5 242.2v2.8z"/>
<path d="M377.8 242.2h1.7z"/>
<path d="M377.8 242.2l-.6 .6z"/>
<path d="M377.2 242.8v1.1z"/>
<path d="M377.2 243.9l.6 .5z"/>
<path d="M377.8 244.4h1.7z"/>
<path d="M385.7 241.1l.6 .5z"/>
<path d="M384.6 241.1h1.1z"/>
<path d="M384 241.6l.6-.5z"/>
<path d="M384 241.6v2.3z"/>
<path d="M384 243.9l.6 .5z"/>
<path d="M384.6 244.4h1.1z"/>
<path d="M385.7 244.4l.6-.5z"/>
<path d="M387.4 242.2v2.2z"/>
<path d="M387.4 243.3l1.2-1.1z"/>
<path d="M388.6 242.2h.5z"/>
<path d="M390.8 242.2h1.1z"/>
<path d="M391.9 242.2l.6 .6z"/>
<path d="M392.5 242.8v1.6z"/>
<path d="M390.8 244.4h1.7z"/>
<path d="M390.2 243.9l.6 .5z"/>
<path d="M390.2 243.9l.6-.6z"/>
<path d="M390.8 243.3h1.7z"/>
<path d="M394.2 241.6v2.8z"/>
<path d="M394.2 241.6l.6-.5z"/>
<path d="M393.7 242.8h1.1z"/>
<path d="M396.5 241.6v2.3z"/>
<path d="M396.5 243.9l.6 .5z"/>
<path d="M395.9 242.2h1.2z"/>
</g>
<g fill="#800000" stroke="#800000" stroke-width=".21">
<path d="M117.6 192.5h3.9v.5h-3.9z"/>
<path d="M117.6 191.5h3.9v.5h-3.9z"/>
<path d="M129.9 192.5h3.9v.5h-3.9z"/>
<path d="M129.9 191.5h3.9v.5h-3.9z"/>
<path d="M105.3 192.5h3.9v.5h-3.9z"/>
<path d="M105.3 191.5h3.9v.5h-3.9z"/>
<path d="M295 54.5h4v.5h-4z"/>
<path d="M295 53.5h4v.5h-4z"/>
</g>
<g fill="#000080" stroke="#000080" stroke-width=".74">
<path d="M373.4 90v36.9z"/>
<path d="M373.4 126.9h2.5z"/>
</g>
<g fill="#008000" stroke="#008000" stroke-width=".21">
<path d="M356.1 90h17.3z"/>
<path d="M356.1 94.9h17.3z"/>
<path d="M151.6 193.5h7.4z"/>
<path d="M151.6 193.5v2.4z"/>
<path d="M151.6 195.9v2.5z"/>
<path d="M151.6 198.4v4.9z"/>
<path d="M151.6 195.9h7.4z"/>
<path d="M151.6 198.4h7.4z"/>
<path d="M131.9 195.9v2.5z"/>
<path d="M119.5 198.4h12.4z"/>
<path d="M107.2 198.4h12.3z"/>
<path d="M107.2 198.4v4.9z"/>
<path d="M107.2 195.9v2.5z"/>
<path d="M119.5 195.9v2.5z"/>
<path d="M141.7 60.4h14.8z"/>
<path d="M156.5 60.4v17.3z"/>
<path d="M156.5 77.7v17.2z"/>
<path d="M156.5 94.9v17.3z"/>
<path d="M156.5 112.2v17.2z"/>
<path d="M156.5 129.4v9.9z"/>
<path d="M141.7 77.7h14.8z"/>
<path d="M141.7 94.9h14.8z"/>
<path d="M141.7 112.2h14.8z"/>
<path d="M141.7 129.4h14.8z"/>
<path d="M252.6 195.9h12.3z"/>
<path d="M264.9 195.9v7.4z"/>
<path d="M274.8 70.3h4.9z"/>
<path d="M279.7 70.3v9.8z"/>
<path d="M114.6 144.2v4.9z"/>
<path d="M297 57.9v2.5z"/>
<path d="M385.7 104.8v2.4z"/>
<path d="M151.6 186.1h7.4z"/>
<path d="M151.6 181.1v5z"/>
<path d="M151.6 188.5h7.4z"/>
<path d="M151.6 186.1v2.4z"/>
<path d="M151.6 191h7.4z"/>
<path d="M151.6 188.5v2.5z"/>
<path d="M141.7 126.9h19.7z"/>
<path d="M161.4 109.7v17.2z"/>
<path d="M161.4 92.4v17.3z"/>
<path d="M161.4 75.2v17.2z"/>
<path d="M161.4 57.9v17.3z"/>
<path d="M161.4 48.1v9.8z"/>
<path d="M141.7 109.7h19.7z"/>
<path d="M141.7 92.4h19.7z"/>
<path d="M141.7 75.2h19.7z"/>
<path d="M141.7 57.9h19.7z"/>
<path d="M252.6 198.4h7.4z"/>
<path d="M260 181.1v17.3z"/>
<path d="M247.7 48.1v2.4z"/>
<path d="M274.8 67.8h4.9z"/>
<path d="M279.7 48.1v19.7z"/>
<path d="M131.9 186.1v2.4z"/>
<path d="M119.5 186.1h12.4z"/>
<path d="M119.5 186.1v2.4z"/>
<path d="M107.2 186.1h12.3z"/>
<path d="M107.2 186.1v2.4z"/>
<path d="M107.2 181.1v5z"/>
<path d="M297 48.1v2.4z"/>
<path d="M225.5 55.5v4.9z"/>
<path d="M186.1 55.5v4.9z"/>
<path d="M186.1 55.5h9.8z"/>
<path d="M195.9 55.5h9.9z"/>
<path d="M205.8 55.5h9.9z"/>
<path d="M215.7 55.5h9.8z"/>
<path d="M195.9 55.5v4.9z"/>
<path d="M205.8 55.5v4.9z"/>
<path d="M215.7 55.5v4.9z"/>
<path d="M186.1 48.1v7.4z"/>
<path d="M186.1 70.3v46.8z"/>
<path d="M186.1 117.1h142.9z"/>
<path d="M141.7 131.9h29.6z"/>
<path d="M171.3 117.1v14.8z"/>
<path d="M171.3 117.1h14.8z"/>
<path d="M141.7 62.9h29.6z"/>
<path d="M171.3 62.9v29.5z"/>
<path d="M171.3 92.4h54.2z"/>
<path d="M225.5 70.3v22.1z"/>
<path d="M225.5 92.4h103.5z"/>
<path d="M141.7 80.1h24.7z"/>
<path d="M166.4 80.1v14.8z"/>
<path d="M166.4 94.9h49.3z"/>
<path d="M215.7 70.3v24.6z"/>
<path d="M215.7 94.9h113.3z"/>
<path d="M141.7 97.4h64.1z"/>
<path d="M205.8 70.3v27.1z"/>
<path d="M205.8 97.4h123.2z"/>
<path d="M141.7 114.6h24.7z"/>
<path d="M166.4 99.8v14.8z"/>
<path d="M166.4 99.8h29.5z"/>
<path d="M195.9 70.3v29.5z"/>
<path d="M195.9 99.8h133.1z"/>
<path d="M252.6 186.1h32.1z"/>
<path d="M252.6 188.5h32.1z"/>
<path d="M252.6 191h32.1z"/>
<path d="M252.6 193.5h32.1z"/>
<path d="M247.7 60.4v2.5z"/>
<path d="M247.7 62.9h4.9z"/>
<path d="M274.8 62.9h9.9z"/>
<path d="M284.7 62.9v14.8z"/>
<path d="M284.7 77.7h44.3z"/>
<path d="M114.6 129.4h2.5z"/>
<path d="M114.6 129.4v2.5z"/>
<path d="M114.6 131.9v2.4z"/>
<path d="M114.6 60.4h2.5z"/>
<path d="M114.6 60.4v17.3z"/>
<path d="M114.6 77.7h2.5z"/>
<path d="M114.6 77.7v17.2z"/>
<path d="M114.6 94.9h2.5z"/>
<path d="M114.6 94.9v17.3z"/>
<path d="M114.6 112.2v17.2z"/>
<path d="M114.6 112.2h2.5z"/>
<path d="M77.6 97.4v34.5z"/>
<path d="M43.1 97.4h34.5z"/>
<path d="M77.6 131.9h37z"/>
<path d="M43.1 87.5h34.5z"/>
<path d="M77.6 57.9v29.6z"/>
<path d="M77.6 57.9h17.3z"/>
<path d="M43.1 90h39.5z"/>
<path d="M82.6 75.2v14.8z"/>
<path d="M82.6 75.2h12.3z"/>
<path d="M43.1 94.9h44.4z"/>
<path d="M87.5 94.9v14.8z"/>
<path d="M87.5 109.7h7.4z"/>
<path d="M82.6 99.8v27.1z"/>
<path d="M43.1 99.8h39.5z"/>
<path d="M82.6 126.9h12.3z"/>
<path d="M356.1 104.8h17.3z"/>
<path d="M356.1 109.7h17.3z"/>
<path d="M356.1 97.4h17.3z"/>
<path d="M356.1 99.8h17.3z"/>
<path d="M104.8 57.9h12.3z"/>
<path d="M104.8 75.2h12.3z"/>
<path d="M104.8 92.4h12.3z"/>
<path d="M104.8 109.7h12.3z"/>
<path d="M104.8 126.9h12.3z"/>
<path d="M43.1 92.4h51.8z"/>
<path d="M385.7 90v7.4z"/>
<path d="M385.7 77.7v2.4z"/>
<path d="M356.1 77.7h29.6z"/>
<circle cx="151.6" cy="195.9" r=".49"/>
<circle cx="151.6" cy="198.4" r=".49"/>
<circle cx="107.2" cy="198.4" r=".49"/>
<circle cx="119.5" cy="198.4" r=".49"/>
<circle cx="156.5" cy="77.7" r=".49"/>
<circle cx="156.5" cy="94.9" r=".49"/>
<circle cx="156.5" cy="112.2" r=".49"/>
<circle cx="156.5" cy="129.4" r=".49"/>
<circle cx="151.6" cy="186.1" r=".49"/>
<circle cx="151.6" cy="188.5" r=".49"/>
<circle cx="161.4" cy="109.7" r=".49"/>
<circle cx="161.4" cy="92.4" r=".49"/>
<circle cx="161.4" cy="75.2" r=".49"/>
<circle cx="161.4" cy="57.9" r=".49"/>
<circle cx="119.5" cy="186.1" r=".49"/>
<circle cx="107.2" cy="186.1" r=".49"/>
<circle cx="195.9" cy="55.5" r=".49"/>
<circle cx="205.8" cy="55.5" r=".49"/>
<circle cx="215.7" cy="55.5" r=".49"/>
<circle cx="186.1" cy="55.5" r=".49"/>
<circle cx="186.1" cy="117.1" r=".49"/>
<circle cx="225.5" cy="92.4" r=".49"/>
<circle cx="215.7" cy="94.9" r=".49"/>
<circle cx="205.8" cy="97.4" r=".49"/>
<circle cx="195.9" cy="99.8" r=".49"/>
<circle cx="114.6" cy="129.4" r=".49"/>
<circle cx="114.6" cy="77.7" r=".49"/>
<circle cx="114.6" cy="94.9" r=".49"/>
<circle cx="114.6" cy="112.2" r=".49"/>
<circle cx="114.6" cy="131.9" r=".49"/>
</g>
<use href="#words"/>
</svg>
